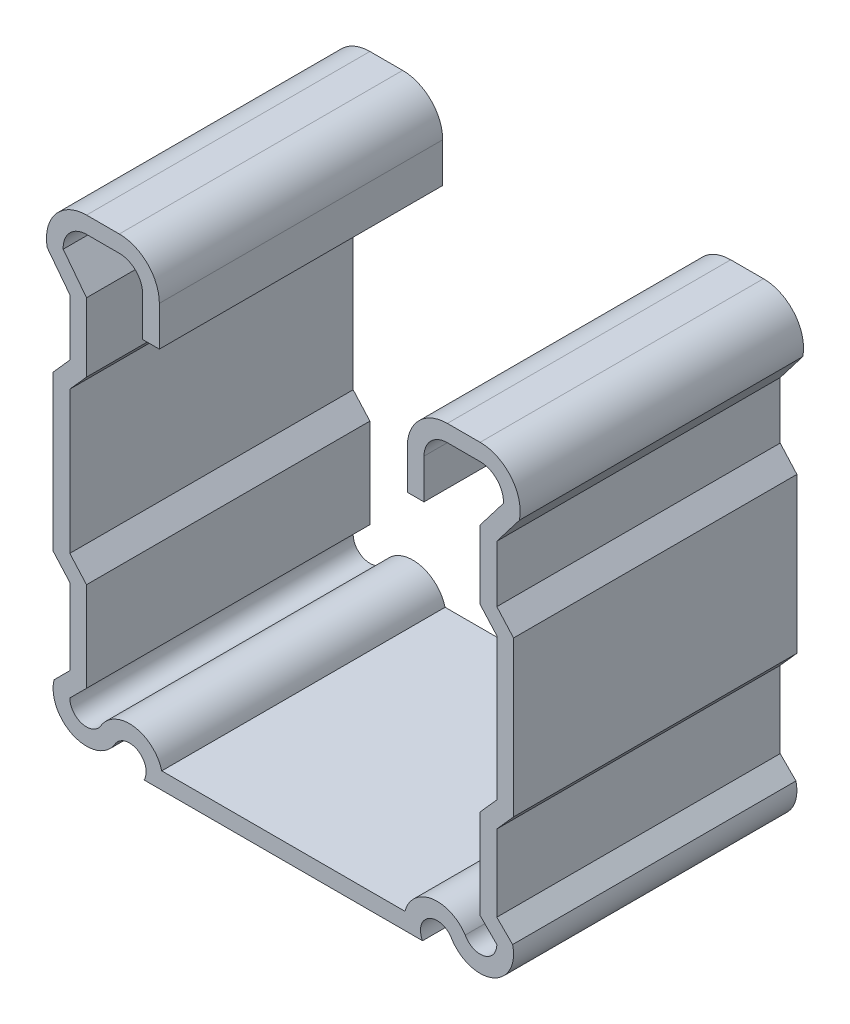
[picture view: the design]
ISO-10303-21;
HEADER;
FILE_DESCRIPTION(('STEP AP214'),'2;1');
FILE_NAME('part.step','',(''),(''),'','','');
FILE_SCHEMA(('AUTOMOTIVE_DESIGN { 1 0 10303 214 1 1 1 1 }'));
ENDSEC;
DATA;
#1=APPLICATION_CONTEXT('core data for automotive mechanical design processes');
#2=APPLICATION_PROTOCOL_DEFINITION('international standard','automotive_design',2000,#1);
#3=PRODUCT_CONTEXT('',#1,'mechanical');
#4=PRODUCT('Part','Part','',(#3));
#5=PRODUCT_RELATED_PRODUCT_CATEGORY('part','',(#4));
#6=PRODUCT_DEFINITION_FORMATION('','',#4);
#7=PRODUCT_DEFINITION_CONTEXT('part definition',#1,'design');
#8=PRODUCT_DEFINITION('design','',#6,#7);
#9=PRODUCT_DEFINITION_SHAPE('','',#8);
#10=(LENGTH_UNIT() NAMED_UNIT(*) SI_UNIT(.MILLI.,.METRE.));
#11=(NAMED_UNIT(*) PLANE_ANGLE_UNIT() SI_UNIT($,.RADIAN.));
#12=(NAMED_UNIT(*) SI_UNIT($,.STERADIAN.) SOLID_ANGLE_UNIT());
#13=UNCERTAINTY_MEASURE_WITH_UNIT(LENGTH_MEASURE(1.E-05),#10,'distance_accuracy_value','');
#14=(GEOMETRIC_REPRESENTATION_CONTEXT(3) GLOBAL_UNCERTAINTY_ASSIGNED_CONTEXT((#13)) GLOBAL_UNIT_ASSIGNED_CONTEXT((#10,
#11,#12)) REPRESENTATION_CONTEXT('',''));
#15=CARTESIAN_POINT('',(0.,0.,0.));
#16=DIRECTION('',(0.,0.,1.));
#17=DIRECTION('',(1.,0.,0.));
#18=AXIS2_PLACEMENT_3D('',#15,#16,#17);
#19=CARTESIAN_POINT('',(13.7938113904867,-17.794678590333,12.7));
#20=DIRECTION('',(0.,0.,-1.));
#21=DIRECTION('',(-1.,0.,0.));
#22=AXIS2_PLACEMENT_3D('',#19,#20,#21);
#23=CYLINDRICAL_SURFACE('',#22,2.9972);
#24=CARTESIAN_POINT('',(13.7938113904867,-17.794678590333,-12.7));
#25=DIRECTION('',(0.,0.,1.));
#26=DIRECTION('',(1.,0.,0.));
#27=AXIS2_PLACEMENT_3D('',#24,#25,#26);
#28=CIRCLE('',#27,2.9972);
#29=CARTESIAN_POINT('',(16.3051886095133,-16.158771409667,-12.7));
#30=VERTEX_POINT('',#29);
#31=CARTESIAN_POINT('',(10.8989921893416,-17.018,-12.7));
#32=VERTEX_POINT('',#31);
#33=EDGE_CURVE('E417',#30,#32,#28,.T.);
#34=ORIENTED_EDGE('',*,*,#33,.T.);
#35=DIRECTION('',(0.,0.,-1.));
#36=VECTOR('',#35,1.);
#37=CARTESIAN_POINT('',(10.8989921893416,-17.018,12.7));
#38=LINE('',#37,#36);
#39=CARTESIAN_POINT('',(10.8989921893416,-17.018,12.7));
#40=VERTEX_POINT('',#39);
#41=EDGE_CURVE('E11',#40,#32,#38,.T.);
#42=ORIENTED_EDGE('',*,*,#41,.F.);
#43=CARTESIAN_POINT('',(13.7938113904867,-17.794678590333,12.7));
#44=DIRECTION('',(0.,0.,1.));
#45=DIRECTION('',(1.,0.,0.));
#46=AXIS2_PLACEMENT_3D('',#43,#44,#45);
#47=CIRCLE('',#46,2.9972);
#48=CARTESIAN_POINT('',(16.3051886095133,-16.158771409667,12.7));
#49=VERTEX_POINT('',#48);
#50=EDGE_CURVE('E527',#49,#40,#47,.T.);
#51=ORIENTED_EDGE('',*,*,#50,.F.);
#52=DIRECTION('',(0.,0.,-1.));
#53=VECTOR('',#52,1.);
#54=CARTESIAN_POINT('',(16.3051886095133,-16.158771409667,12.7));
#55=LINE('',#54,#53);
#56=EDGE_CURVE('E413',#49,#30,#55,.T.);
#57=ORIENTED_EDGE('',*,*,#56,.T.);
#58=EDGE_LOOP('',(#34,#42,#51,#57));
#59=FACE_BOUND('',#58,.T.);
#60=ADVANCED_FACE('F33',(#59),#23,.T.);
#61=CARTESIAN_POINT('',(-10.8989921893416,-17.018,12.7));
#62=DIRECTION('',(0.,-1.,0.));
#63=DIRECTION('',(1.,0.,0.));
#64=AXIS2_PLACEMENT_3D('',#61,#62,#63);
#65=PLANE('',#64);
#66=DIRECTION('',(-1.,0.,0.));
#67=VECTOR('',#66,1.);
#68=CARTESIAN_POINT('',(-10.8989921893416,-17.018,-12.7));
#69=LINE('',#68,#67);
#70=CARTESIAN_POINT('',(-10.8989921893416,-17.018,-12.7));
#71=VERTEX_POINT('',#70);
#72=EDGE_CURVE('E420',#32,#71,#69,.T.);
#73=ORIENTED_EDGE('',*,*,#72,.T.);
#74=DIRECTION('',(0.,0.,-1.));
#75=VECTOR('',#74,1.);
#76=CARTESIAN_POINT('',(-10.8989921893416,-17.018,12.7));
#77=LINE('',#76,#75);
#78=CARTESIAN_POINT('',(-10.8989921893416,-17.018,12.7));
#79=VERTEX_POINT('',#78);
#80=EDGE_CURVE('E41',#79,#71,#77,.T.);
#81=ORIENTED_EDGE('',*,*,#80,.F.);
#82=DIRECTION('',(-1.,0.,0.));
#83=VECTOR('',#82,1.);
#84=CARTESIAN_POINT('',(-10.8989921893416,-17.018,12.7));
#85=LINE('',#84,#83);
#86=EDGE_CURVE('E236',#40,#79,#85,.T.);
#87=ORIENTED_EDGE('',*,*,#86,.F.);
#88=ORIENTED_EDGE('',*,*,#41,.T.);
#89=EDGE_LOOP('',(#73,#81,#87,#88));
#90=FACE_BOUND('',#89,.T.);
#91=ADVANCED_FACE('F825',(#90),#65,.F.);
#92=CARTESIAN_POINT('',(-13.7938113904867,-17.794678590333,12.7));
#93=DIRECTION('',(0.,0.,-1.));
#94=DIRECTION('',(-1.,0.,0.));
#95=AXIS2_PLACEMENT_3D('',#92,#93,#94);
#96=CYLINDRICAL_SURFACE('',#95,2.9972);
#97=CARTESIAN_POINT('',(-13.7938113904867,-17.794678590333,-12.7));
#98=DIRECTION('',(0.,0.,1.));
#99=DIRECTION('',(-1.,0.,0.));
#100=AXIS2_PLACEMENT_3D('',#97,#98,#99);
#101=CIRCLE('',#100,2.9972);
#102=CARTESIAN_POINT('',(-16.4142858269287,-16.3399203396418,-12.7));
#103=VERTEX_POINT('',#102);
#104=EDGE_CURVE('E422',#71,#103,#101,.T.);
#105=ORIENTED_EDGE('',*,*,#104,.T.);
#106=DIRECTION('',(0.,0.,-1.));
#107=VECTOR('',#106,1.);
#108=CARTESIAN_POINT('',(-16.4142858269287,-16.3399203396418,12.7));
#109=LINE('',#108,#107);
#110=CARTESIAN_POINT('',(-16.4142858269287,-16.3399203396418,12.7));
#111=VERTEX_POINT('',#110);
#112=EDGE_CURVE('E678',#111,#103,#109,.T.);
#113=ORIENTED_EDGE('',*,*,#112,.F.);
#114=CARTESIAN_POINT('',(-13.7938113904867,-17.794678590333,12.7));
#115=DIRECTION('',(0.,0.,1.));
#116=DIRECTION('',(-1.,0.,0.));
#117=AXIS2_PLACEMENT_3D('',#114,#115,#116);
#118=CIRCLE('',#117,2.9972);
#119=EDGE_CURVE('E686',#79,#111,#118,.T.);
#120=ORIENTED_EDGE('',*,*,#119,.F.);
#121=ORIENTED_EDGE('',*,*,#80,.T.);
#122=EDGE_LOOP('',(#105,#113,#120,#121));
#123=FACE_BOUND('',#122,.T.);
#124=ADVANCED_FACE('F684',(#123),#96,.T.);
#125=CARTESIAN_POINT('',(-17.6403,-15.478125,12.7));
#126=DIRECTION('',(0.,0.,-1.));
#127=DIRECTION('',(-1.,0.,0.));
#128=AXIS2_PLACEMENT_3D('',#125,#126,#127);
#129=CYLINDRICAL_SURFACE('',#128,1.4986);
#130=CARTESIAN_POINT('',(-17.6403,-15.478125,-12.7));
#131=DIRECTION('',(0.,0.,-1.));
#132=DIRECTION('',(1.,0.,0.));
#133=AXIS2_PLACEMENT_3D('',#130,#131,#132);
#134=CIRCLE('',#133,1.4986);
#135=CARTESIAN_POINT('',(-19.1389,-15.478125,-12.7));
#136=VERTEX_POINT('',#135);
#137=EDGE_CURVE('E424',#103,#136,#134,.T.);
#138=ORIENTED_EDGE('',*,*,#137,.T.);
#139=DIRECTION('',(0.,0.,-1.));
#140=VECTOR('',#139,1.);
#141=CARTESIAN_POINT('',(-19.1389,-15.478125,12.7));
#142=LINE('',#141,#140);
#143=CARTESIAN_POINT('',(-19.1389,-15.478125,12.7));
#144=VERTEX_POINT('',#143);
#145=EDGE_CURVE('E675',#144,#136,#142,.T.);
#146=ORIENTED_EDGE('',*,*,#145,.F.);
#147=CARTESIAN_POINT('',(-17.6403,-15.478125,12.7));
#148=DIRECTION('',(0.,0.,-1.));
#149=DIRECTION('',(1.,0.,0.));
#150=AXIS2_PLACEMENT_3D('',#147,#148,#149);
#151=CIRCLE('',#150,1.4986);
#152=EDGE_CURVE('E704',#111,#144,#151,.T.);
#153=ORIENTED_EDGE('',*,*,#152,.F.);
#154=ORIENTED_EDGE('',*,*,#112,.T.);
#155=EDGE_LOOP('',(#138,#146,#153,#154));
#156=FACE_BOUND('',#155,.T.);
#157=ADVANCED_FACE('F695',(#156),#129,.F.);
#158=CARTESIAN_POINT('',(-17.6403,-13.979525,12.7));
#159=DIRECTION('',(-0.707106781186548,0.707106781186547,0.));
#160=DIRECTION('',(-0.707106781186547,-0.707106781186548,0.));
#161=AXIS2_PLACEMENT_3D('',#158,#159,#160);
#162=PLANE('',#161);
#163=DIRECTION('',(0.707106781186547,0.707106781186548,0.));
#164=VECTOR('',#163,1.);
#165=CARTESIAN_POINT('',(-17.6403,-13.979525,-12.7));
#166=LINE('',#165,#164);
#167=CARTESIAN_POINT('',(-17.6403,-13.979525,-12.7));
#168=VERTEX_POINT('',#167);
#169=EDGE_CURVE('E426',#136,#168,#166,.T.);
#170=ORIENTED_EDGE('',*,*,#169,.T.);
#171=DIRECTION('',(0.,0.,-1.));
#172=VECTOR('',#171,1.);
#173=CARTESIAN_POINT('',(-17.6403,-13.979525,12.7));
#174=LINE('',#173,#172);
#175=CARTESIAN_POINT('',(-17.6403,-13.979525,12.7));
#176=VERTEX_POINT('',#175);
#177=EDGE_CURVE('E672',#176,#168,#174,.T.);
#178=ORIENTED_EDGE('',*,*,#177,.F.);
#179=DIRECTION('',(0.707106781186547,0.707106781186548,0.));
#180=VECTOR('',#179,1.);
#181=CARTESIAN_POINT('',(-17.6403,-13.979525,12.7));
#182=LINE('',#181,#180);
#183=EDGE_CURVE('E701',#144,#176,#182,.T.);
#184=ORIENTED_EDGE('',*,*,#183,.F.);
#185=ORIENTED_EDGE('',*,*,#145,.T.);
#186=EDGE_LOOP('',(#170,#178,#184,#185));
#187=FACE_BOUND('',#186,.T.);
#188=ADVANCED_FACE('F699',(#187),#162,.F.);
#189=CARTESIAN_POINT('',(-17.6403,-13.979525,12.7));
#190=DIRECTION('',(-1.,0.,0.));
#191=DIRECTION('',(0.,-1.,0.));
#192=AXIS2_PLACEMENT_3D('',#189,#190,#191);
#193=PLANE('',#192);
#194=DIRECTION('',(0.,1.,0.));
#195=VECTOR('',#194,1.);
#196=CARTESIAN_POINT('',(-17.6403,-13.979525,-12.7));
#197=LINE('',#196,#195);
#198=CARTESIAN_POINT('',(-17.6403,-5.93680201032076,-12.7));
#199=VERTEX_POINT('',#198);
#200=EDGE_CURVE('E428',#168,#199,#197,.T.);
#201=ORIENTED_EDGE('',*,*,#200,.T.);
#202=DIRECTION('',(0.,0.,-1.));
#203=VECTOR('',#202,1.);
#204=CARTESIAN_POINT('',(-17.6403,-5.93680201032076,12.7));
#205=LINE('',#204,#203);
#206=CARTESIAN_POINT('',(-17.6403,-5.93680201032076,12.7));
#207=VERTEX_POINT('',#206);
#208=EDGE_CURVE('E669',#207,#199,#205,.T.);
#209=ORIENTED_EDGE('',*,*,#208,.F.);
#210=DIRECTION('',(0.,1.,0.));
#211=VECTOR('',#210,1.);
#212=CARTESIAN_POINT('',(-17.6403,-13.979525,12.7));
#213=LINE('',#212,#211);
#214=EDGE_CURVE('E703',#176,#207,#213,.T.);
#215=ORIENTED_EDGE('',*,*,#214,.F.);
#216=ORIENTED_EDGE('',*,*,#177,.T.);
#217=EDGE_LOOP('',(#201,#209,#215,#216));
#218=FACE_BOUND('',#217,.T.);
#219=ADVANCED_FACE('F838',(#218),#193,.F.);
#220=CARTESIAN_POINT('',(-17.6403,-5.93680201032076,12.7));
#221=DIRECTION('',(-0.746819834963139,-0.665026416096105,0.));
#222=DIRECTION('',(0.665026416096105,-0.746819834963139,0.));
#223=AXIS2_PLACEMENT_3D('',#220,#221,#222);
#224=PLANE('',#223);
#225=DIRECTION('',(-0.665026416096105,0.746819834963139,0.));
#226=VECTOR('',#225,1.);
#227=CARTESIAN_POINT('',(-17.6403,-5.93680201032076,-12.7));
#228=LINE('',#227,#226);
#229=CARTESIAN_POINT('',(-19.1389,-4.25388509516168,-12.7));
#230=VERTEX_POINT('',#229);
#231=EDGE_CURVE('E430',#199,#230,#228,.T.);
#232=ORIENTED_EDGE('',*,*,#231,.T.);
#233=DIRECTION('',(0.,0.,-1.));
#234=VECTOR('',#233,1.);
#235=CARTESIAN_POINT('',(-19.1389,-4.25388509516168,12.7));
#236=LINE('',#235,#234);
#237=CARTESIAN_POINT('',(-19.1389,-4.25388509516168,12.7));
#238=VERTEX_POINT('',#237);
#239=EDGE_CURVE('E666',#238,#230,#236,.T.);
#240=ORIENTED_EDGE('',*,*,#239,.F.);
#241=DIRECTION('',(-0.665026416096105,0.746819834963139,0.));
#242=VECTOR('',#241,1.);
#243=CARTESIAN_POINT('',(-17.6403,-5.93680201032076,12.7));
#244=LINE('',#243,#242);
#245=EDGE_CURVE('E706',#207,#238,#244,.T.);
#246=ORIENTED_EDGE('',*,*,#245,.F.);
#247=ORIENTED_EDGE('',*,*,#208,.T.);
#248=EDGE_LOOP('',(#232,#240,#246,#247));
#249=FACE_BOUND('',#248,.T.);
#250=ADVANCED_FACE('F841',(#249),#224,.F.);
#251=CARTESIAN_POINT('',(-19.1389,-4.25388509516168,12.7));
#252=DIRECTION('',(-1.,0.,0.));
#253=DIRECTION('',(0.,0.,1.));
#254=AXIS2_PLACEMENT_3D('',#251,#252,#253);
#255=PLANE('',#254);
#256=DIRECTION('',(0.,1.,0.));
#257=VECTOR('',#256,1.);
#258=CARTESIAN_POINT('',(-19.1389,-4.25388509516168,-12.7));
#259=LINE('',#258,#257);
#260=CARTESIAN_POINT('',(-19.1389,8.49568509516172,-12.7));
#261=VERTEX_POINT('',#260);
#262=EDGE_CURVE('E432',#230,#261,#259,.T.);
#263=ORIENTED_EDGE('',*,*,#262,.T.);
#264=DIRECTION('',(0.,0.,-1.));
#265=VECTOR('',#264,1.);
#266=CARTESIAN_POINT('',(-19.1389,8.49568509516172,12.7));
#267=LINE('',#266,#265);
#268=CARTESIAN_POINT('',(-19.1389,8.49568509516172,12.7));
#269=VERTEX_POINT('',#268);
#270=EDGE_CURVE('E663',#269,#261,#267,.T.);
#271=ORIENTED_EDGE('',*,*,#270,.F.);
#272=DIRECTION('',(0.,1.,0.));
#273=VECTOR('',#272,1.);
#274=CARTESIAN_POINT('',(-19.1389,-4.25388509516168,12.7));
#275=LINE('',#274,#273);
#276=EDGE_CURVE('E712',#238,#269,#275,.T.);
#277=ORIENTED_EDGE('',*,*,#276,.F.);
#278=ORIENTED_EDGE('',*,*,#239,.T.);
#279=EDGE_LOOP('',(#263,#271,#277,#278));
#280=FACE_BOUND('',#279,.T.);
#281=ADVANCED_FACE('F845',(#280),#255,.F.);
#282=CARTESIAN_POINT('',(-17.6403,10.178602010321,12.7));
#283=DIRECTION('',(-0.746819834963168,0.665026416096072,0.));
#284=DIRECTION('',(-0.665026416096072,-0.746819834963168,0.));
#285=AXIS2_PLACEMENT_3D('',#282,#283,#284);
#286=PLANE('',#285);
#287=DIRECTION('',(0.665026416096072,0.746819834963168,0.));
#288=VECTOR('',#287,1.);
#289=CARTESIAN_POINT('',(-17.6403,10.178602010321,-12.7));
#290=LINE('',#289,#288);
#291=CARTESIAN_POINT('',(-17.6403,10.178602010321,-12.7));
#292=VERTEX_POINT('',#291);
#293=EDGE_CURVE('E434',#261,#292,#290,.T.);
#294=ORIENTED_EDGE('',*,*,#293,.T.);
#295=DIRECTION('',(0.,0.,-1.));
#296=VECTOR('',#295,1.);
#297=CARTESIAN_POINT('',(-17.6403,10.178602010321,12.7));
#298=LINE('',#297,#296);
#299=CARTESIAN_POINT('',(-17.6403,10.178602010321,12.7));
#300=VERTEX_POINT('',#299);
#301=EDGE_CURVE('E660',#300,#292,#298,.T.);
#302=ORIENTED_EDGE('',*,*,#301,.F.);
#303=DIRECTION('',(0.665026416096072,0.746819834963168,0.));
#304=VECTOR('',#303,1.);
#305=CARTESIAN_POINT('',(-17.6403,10.178602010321,12.7));
#306=LINE('',#305,#304);
#307=EDGE_CURVE('E714',#269,#300,#306,.T.);
#308=ORIENTED_EDGE('',*,*,#307,.F.);
#309=ORIENTED_EDGE('',*,*,#270,.T.);
#310=EDGE_LOOP('',(#294,#302,#308,#309));
#311=FACE_BOUND('',#310,.T.);
#312=ADVANCED_FACE('F849',(#311),#286,.F.);
#313=CARTESIAN_POINT('',(-17.6403,10.178602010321,12.7));
#314=DIRECTION('',(-1.,0.,0.));
#315=DIRECTION('',(0.,0.,1.));
#316=AXIS2_PLACEMENT_3D('',#313,#314,#315);
#317=PLANE('',#316);
#318=DIRECTION('',(0.,1.,0.));
#319=VECTOR('',#318,1.);
#320=CARTESIAN_POINT('',(-17.6403,10.178602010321,-12.7));
#321=LINE('',#320,#319);
#322=CARTESIAN_POINT('',(-17.6403,16.3392865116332,-12.7));
#323=VERTEX_POINT('',#322);
#324=EDGE_CURVE('E436',#292,#323,#321,.T.);
#325=ORIENTED_EDGE('',*,*,#324,.T.);
#326=DIRECTION('',(0.,0.,-1.));
#327=VECTOR('',#326,1.);
#328=CARTESIAN_POINT('',(-17.6403,16.3392865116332,12.7));
#329=LINE('',#328,#327);
#330=CARTESIAN_POINT('',(-17.6403,16.3392865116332,12.7));
#331=VERTEX_POINT('',#330);
#332=EDGE_CURVE('E657',#331,#323,#329,.T.);
#333=ORIENTED_EDGE('',*,*,#332,.F.);
#334=DIRECTION('',(0.,1.,0.));
#335=VECTOR('',#334,1.);
#336=CARTESIAN_POINT('',(-17.6403,10.178602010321,12.7));
#337=LINE('',#336,#335);
#338=EDGE_CURVE('E716',#300,#331,#337,.T.);
#339=ORIENTED_EDGE('',*,*,#338,.F.);
#340=ORIENTED_EDGE('',*,*,#301,.T.);
#341=EDGE_LOOP('',(#325,#333,#339,#340));
#342=FACE_BOUND('',#341,.T.);
#343=ADVANCED_FACE('F853',(#342),#317,.F.);
#344=CARTESIAN_POINT('',(-17.6403,16.3392865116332,12.7));
#345=DIRECTION('',(-0.793466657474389,-0.608613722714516,0.));
#346=DIRECTION('',(0.608613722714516,-0.793466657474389,0.));
#347=AXIS2_PLACEMENT_3D('',#344,#345,#346);
#348=PLANE('',#347);
#349=DIRECTION('',(-0.608613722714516,0.793466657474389,0.));
#350=VECTOR('',#349,1.);
#351=CARTESIAN_POINT('',(-17.6403,16.3392865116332,-12.7));
#352=LINE('',#351,#350);
#353=CARTESIAN_POINT('',(-19.7298825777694,19.0635335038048,-12.7));
#354=VERTEX_POINT('',#353);
#355=EDGE_CURVE('E438',#323,#354,#352,.T.);
#356=ORIENTED_EDGE('',*,*,#355,.T.);
#357=DIRECTION('',(0.,0.,-1.));
#358=VECTOR('',#357,1.);
#359=CARTESIAN_POINT('',(-19.7298825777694,19.0635335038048,12.7));
#360=LINE('',#359,#358);
#361=CARTESIAN_POINT('',(-19.7298825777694,19.0635335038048,12.7));
#362=VERTEX_POINT('',#361);
#363=EDGE_CURVE('E654',#362,#354,#360,.T.);
#364=ORIENTED_EDGE('',*,*,#363,.F.);
#365=DIRECTION('',(-0.608613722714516,0.793466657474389,0.));
#366=VECTOR('',#365,1.);
#367=CARTESIAN_POINT('',(-17.6403,16.3392865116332,12.7));
#368=LINE('',#367,#366);
#369=EDGE_CURVE('E718',#331,#362,#368,.T.);
#370=ORIENTED_EDGE('',*,*,#369,.F.);
#371=ORIENTED_EDGE('',*,*,#332,.T.);
#372=EDGE_LOOP('',(#356,#364,#370,#371));
#373=FACE_BOUND('',#372,.T.);
#374=ADVANCED_FACE('F857',(#373),#348,.F.);
#375=CARTESIAN_POINT('',(-17.6403,19.1676263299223,12.7));
#376=DIRECTION('',(0.,0.,-1.));
#377=DIRECTION('',(-1.,0.,0.));
#378=AXIS2_PLACEMENT_3D('',#375,#376,#377);
#379=CYLINDRICAL_SURFACE('',#378,2.09217367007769);
#380=CARTESIAN_POINT('',(-17.6403,19.1676263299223,-12.7));
#381=DIRECTION('',(0.,0.,-1.));
#382=DIRECTION('',(1.,0.,0.));
#383=AXIS2_PLACEMENT_3D('',#380,#381,#382);
#384=CIRCLE('',#383,2.09217367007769);
#385=CARTESIAN_POINT('',(-17.6403,21.2598,-12.7));
#386=VERTEX_POINT('',#385);
#387=EDGE_CURVE('E440',#354,#386,#384,.T.);
#388=ORIENTED_EDGE('',*,*,#387,.T.);
#389=DIRECTION('',(0.,0.,-1.));
#390=VECTOR('',#389,1.);
#391=CARTESIAN_POINT('',(-17.6403,21.2598,12.7));
#392=LINE('',#391,#390);
#393=CARTESIAN_POINT('',(-17.6403,21.2598,12.7));
#394=VERTEX_POINT('',#393);
#395=EDGE_CURVE('E651',#394,#386,#392,.T.);
#396=ORIENTED_EDGE('',*,*,#395,.F.);
#397=CARTESIAN_POINT('',(-17.6403,19.1676263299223,12.7));
#398=DIRECTION('',(0.,0.,-1.));
#399=DIRECTION('',(1.,0.,0.));
#400=AXIS2_PLACEMENT_3D('',#397,#398,#399);
#401=CIRCLE('',#400,2.09217367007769);
#402=EDGE_CURVE('E720',#362,#394,#401,.T.);
#403=ORIENTED_EDGE('',*,*,#402,.F.);
#404=ORIENTED_EDGE('',*,*,#363,.T.);
#405=EDGE_LOOP('',(#388,#396,#403,#404));
#406=FACE_BOUND('',#405,.T.);
#407=ADVANCED_FACE('F861',(#406),#379,.F.);
#408=CARTESIAN_POINT('',(-17.6403,21.2598,12.7));
#409=DIRECTION('',(0.,1.,0.));
#410=DIRECTION('',(0.,0.,1.));
#411=AXIS2_PLACEMENT_3D('',#408,#409,#410);
#412=PLANE('',#411);
#413=DIRECTION('',(1.,0.,0.));
#414=VECTOR('',#413,1.);
#415=CARTESIAN_POINT('',(-17.6403,21.2598,-12.7));
#416=LINE('',#415,#414);
#417=CARTESIAN_POINT('',(-14.7032736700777,21.2598,-12.7));
#418=VERTEX_POINT('',#417);
#419=EDGE_CURVE('E442',#386,#418,#416,.T.);
#420=ORIENTED_EDGE('',*,*,#419,.T.);
#421=DIRECTION('',(0.,0.,-1.));
#422=VECTOR('',#421,1.);
#423=CARTESIAN_POINT('',(-14.7032736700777,21.2598,12.7));
#424=LINE('',#423,#422);
#425=CARTESIAN_POINT('',(-14.7032736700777,21.2598,12.7));
#426=VERTEX_POINT('',#425);
#427=EDGE_CURVE('E648',#426,#418,#424,.T.);
#428=ORIENTED_EDGE('',*,*,#427,.F.);
#429=DIRECTION('',(1.,0.,0.));
#430=VECTOR('',#429,1.);
#431=CARTESIAN_POINT('',(-17.6403,21.2598,12.7));
#432=LINE('',#431,#430);
#433=EDGE_CURVE('E722',#394,#426,#432,.T.);
#434=ORIENTED_EDGE('',*,*,#433,.F.);
#435=ORIENTED_EDGE('',*,*,#395,.T.);
#436=EDGE_LOOP('',(#420,#428,#434,#435));
#437=FACE_BOUND('',#436,.T.);
#438=ADVANCED_FACE('F865',(#437),#412,.F.);
#439=CARTESIAN_POINT('',(-14.7032736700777,19.1676263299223,12.7));
#440=DIRECTION('',(0.,0.,-1.));
#441=DIRECTION('',(-1.,0.,0.));
#442=AXIS2_PLACEMENT_3D('',#439,#440,#441);
#443=CYLINDRICAL_SURFACE('',#442,2.09217367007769);
#444=CARTESIAN_POINT('',(-14.7032736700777,19.1676263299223,-12.7));
#445=DIRECTION('',(0.,0.,-1.));
#446=DIRECTION('',(1.,0.,0.));
#447=AXIS2_PLACEMENT_3D('',#444,#445,#446);
#448=CIRCLE('',#447,2.09217367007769);
#449=CARTESIAN_POINT('',(-12.6111,19.1676263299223,-12.7));
#450=VERTEX_POINT('',#449);
#451=EDGE_CURVE('E444',#418,#450,#448,.T.);
#452=ORIENTED_EDGE('',*,*,#451,.T.);
#453=DIRECTION('',(0.,0.,-1.));
#454=VECTOR('',#453,1.);
#455=CARTESIAN_POINT('',(-12.6111,19.1676263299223,12.7));
#456=LINE('',#455,#454);
#457=CARTESIAN_POINT('',(-12.6111,19.1676263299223,12.7));
#458=VERTEX_POINT('',#457);
#459=EDGE_CURVE('E645',#458,#450,#456,.T.);
#460=ORIENTED_EDGE('',*,*,#459,.F.);
#461=CARTESIAN_POINT('',(-14.7032736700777,19.1676263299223,12.7));
#462=DIRECTION('',(0.,0.,-1.));
#463=DIRECTION('',(1.,0.,0.));
#464=AXIS2_PLACEMENT_3D('',#461,#462,#463);
#465=CIRCLE('',#464,2.09217367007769);
#466=EDGE_CURVE('E724',#426,#458,#465,.T.);
#467=ORIENTED_EDGE('',*,*,#466,.F.);
#468=ORIENTED_EDGE('',*,*,#427,.T.);
#469=EDGE_LOOP('',(#452,#460,#467,#468));
#470=FACE_BOUND('',#469,.T.);
#471=ADVANCED_FACE('F869',(#470),#443,.F.);
#472=CARTESIAN_POINT('',(-12.6111,19.1676263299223,12.7));
#473=DIRECTION('',(1.,0.,0.));
#474=DIRECTION('',(0.,0.,-1.));
#475=AXIS2_PLACEMENT_3D('',#472,#473,#474);
#476=PLANE('',#475);
#477=DIRECTION('',(0.,-1.,0.));
#478=VECTOR('',#477,1.);
#479=CARTESIAN_POINT('',(-12.6111,19.1676263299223,-12.7));
#480=LINE('',#479,#478);
#481=CARTESIAN_POINT('',(-12.6111,15.61465,-12.7));
#482=VERTEX_POINT('',#481);
#483=EDGE_CURVE('E446',#450,#482,#480,.T.);
#484=ORIENTED_EDGE('',*,*,#483,.T.);
#485=DIRECTION('',(0.,0.,-1.));
#486=VECTOR('',#485,1.);
#487=CARTESIAN_POINT('',(-12.6111,15.61465,12.7));
#488=LINE('',#487,#486);
#489=CARTESIAN_POINT('',(-12.6111,15.61465,12.7));
#490=VERTEX_POINT('',#489);
#491=EDGE_CURVE('E642',#490,#482,#488,.T.);
#492=ORIENTED_EDGE('',*,*,#491,.F.);
#493=DIRECTION('',(0.,-1.,0.));
#494=VECTOR('',#493,1.);
#495=CARTESIAN_POINT('',(-12.6111,19.1676263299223,12.7));
#496=LINE('',#495,#494);
#497=EDGE_CURVE('E726',#458,#490,#496,.T.);
#498=ORIENTED_EDGE('',*,*,#497,.F.);
#499=ORIENTED_EDGE('',*,*,#459,.T.);
#500=EDGE_LOOP('',(#484,#492,#498,#499));
#501=FACE_BOUND('',#500,.T.);
#502=ADVANCED_FACE('F873',(#501),#476,.F.);
#503=CARTESIAN_POINT('',(-12.6111,15.61465,12.7));
#504=DIRECTION('',(0.,1.,0.));
#505=DIRECTION('',(0.,0.,1.));
#506=AXIS2_PLACEMENT_3D('',#503,#504,#505);
#507=PLANE('',#506);
#508=DIRECTION('',(1.,0.,0.));
#509=VECTOR('',#508,1.);
#510=CARTESIAN_POINT('',(-12.6111,15.61465,-12.7));
#511=LINE('',#510,#509);
#512=CARTESIAN_POINT('',(-11.1125,15.61465,-12.7));
#513=VERTEX_POINT('',#512);
#514=EDGE_CURVE('E448',#482,#513,#511,.T.);
#515=ORIENTED_EDGE('',*,*,#514,.T.);
#516=DIRECTION('',(0.,0.,-1.));
#517=VECTOR('',#516,1.);
#518=CARTESIAN_POINT('',(-11.1125,15.61465,12.7));
#519=LINE('',#518,#517);
#520=CARTESIAN_POINT('',(-11.1125,15.61465,12.7));
#521=VERTEX_POINT('',#520);
#522=EDGE_CURVE('E639',#521,#513,#519,.T.);
#523=ORIENTED_EDGE('',*,*,#522,.F.);
#524=DIRECTION('',(1.,0.,0.));
#525=VECTOR('',#524,1.);
#526=CARTESIAN_POINT('',(-12.6111,15.61465,12.7));
#527=LINE('',#526,#525);
#528=EDGE_CURVE('E728',#490,#521,#527,.T.);
#529=ORIENTED_EDGE('',*,*,#528,.F.);
#530=ORIENTED_EDGE('',*,*,#491,.T.);
#531=EDGE_LOOP('',(#515,#523,#529,#530));
#532=FACE_BOUND('',#531,.T.);
#533=ADVANCED_FACE('F877',(#532),#507,.F.);
#534=CARTESIAN_POINT('',(-11.1125,19.1676263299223,12.7));
#535=DIRECTION('',(-1.,0.,0.));
#536=DIRECTION('',(0.,0.,1.));
#537=AXIS2_PLACEMENT_3D('',#534,#535,#536);
#538=PLANE('',#537);
#539=DIRECTION('',(0.,1.,0.));
#540=VECTOR('',#539,1.);
#541=CARTESIAN_POINT('',(-11.1125,19.1676263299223,-12.7));
#542=LINE('',#541,#540);
#543=CARTESIAN_POINT('',(-11.1125,19.1676263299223,-12.7));
#544=VERTEX_POINT('',#543);
#545=EDGE_CURVE('E450',#513,#544,#542,.T.);
#546=ORIENTED_EDGE('',*,*,#545,.T.);
#547=DIRECTION('',(0.,0.,-1.));
#548=VECTOR('',#547,1.);
#549=CARTESIAN_POINT('',(-11.1125,19.1676263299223,12.7));
#550=LINE('',#549,#548);
#551=CARTESIAN_POINT('',(-11.1125,19.1676263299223,12.7));
#552=VERTEX_POINT('',#551);
#553=EDGE_CURVE('E636',#552,#544,#550,.T.);
#554=ORIENTED_EDGE('',*,*,#553,.F.);
#555=DIRECTION('',(0.,1.,0.));
#556=VECTOR('',#555,1.);
#557=CARTESIAN_POINT('',(-11.1125,19.1676263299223,12.7));
#558=LINE('',#557,#556);
#559=EDGE_CURVE('E730',#521,#552,#558,.T.);
#560=ORIENTED_EDGE('',*,*,#559,.F.);
#561=ORIENTED_EDGE('',*,*,#522,.T.);
#562=EDGE_LOOP('',(#546,#554,#560,#561));
#563=FACE_BOUND('',#562,.T.);
#564=ADVANCED_FACE('F881',(#563),#538,.F.);
#565=CARTESIAN_POINT('',(-14.7032736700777,19.1676263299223,12.7));
#566=DIRECTION('',(0.,0.,-1.));
#567=DIRECTION('',(-1.,0.,0.));
#568=AXIS2_PLACEMENT_3D('',#565,#566,#567);
#569=CYLINDRICAL_SURFACE('',#568,3.59077367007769);
#570=CARTESIAN_POINT('',(-14.7032736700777,19.1676263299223,-12.7));
#571=DIRECTION('',(0.,0.,1.));
#572=DIRECTION('',(1.,0.,0.));
#573=AXIS2_PLACEMENT_3D('',#570,#571,#572);
#574=CIRCLE('',#573,3.59077367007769);
#575=CARTESIAN_POINT('',(-14.7032736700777,22.7584,-12.7));
#576=VERTEX_POINT('',#575);
#577=EDGE_CURVE('E452',#544,#576,#574,.T.);
#578=ORIENTED_EDGE('',*,*,#577,.T.);
#579=DIRECTION('',(0.,0.,-1.));
#580=VECTOR('',#579,1.);
#581=CARTESIAN_POINT('',(-14.7032736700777,22.7584,12.7));
#582=LINE('',#581,#580);
#583=CARTESIAN_POINT('',(-14.7032736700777,22.7584,12.7));
#584=VERTEX_POINT('',#583);
#585=EDGE_CURVE('E633',#584,#576,#582,.T.);
#586=ORIENTED_EDGE('',*,*,#585,.F.);
#587=CARTESIAN_POINT('',(-14.7032736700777,19.1676263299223,12.7));
#588=DIRECTION('',(0.,0.,1.));
#589=DIRECTION('',(1.,0.,0.));
#590=AXIS2_PLACEMENT_3D('',#587,#588,#589);
#591=CIRCLE('',#590,3.59077367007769);
#592=EDGE_CURVE('E732',#552,#584,#591,.T.);
#593=ORIENTED_EDGE('',*,*,#592,.F.);
#594=ORIENTED_EDGE('',*,*,#553,.T.);
#595=EDGE_LOOP('',(#578,#586,#593,#594));
#596=FACE_BOUND('',#595,.T.);
#597=ADVANCED_FACE('F885',(#596),#569,.T.);
#598=CARTESIAN_POINT('',(-17.6403,22.7584,12.7));
#599=DIRECTION('',(0.,-1.,0.));
#600=DIRECTION('',(1.,0.,0.));
#601=AXIS2_PLACEMENT_3D('',#598,#599,#600);
#602=PLANE('',#601);
#603=DIRECTION('',(-1.,0.,0.));
#604=VECTOR('',#603,1.);
#605=CARTESIAN_POINT('',(-17.6403,22.7584,-12.7));
#606=LINE('',#605,#604);
#607=CARTESIAN_POINT('',(-17.6403,22.7584,-12.7));
#608=VERTEX_POINT('',#607);
#609=EDGE_CURVE('E454',#576,#608,#606,.T.);
#610=ORIENTED_EDGE('',*,*,#609,.T.);
#611=DIRECTION('',(0.,0.,-1.));
#612=VECTOR('',#611,1.);
#613=CARTESIAN_POINT('',(-17.6403,22.7584,12.7));
#614=LINE('',#613,#612);
#615=CARTESIAN_POINT('',(-17.6403,22.7584,12.7));
#616=VERTEX_POINT('',#615);
#617=EDGE_CURVE('E630',#616,#608,#614,.T.);
#618=ORIENTED_EDGE('',*,*,#617,.F.);
#619=DIRECTION('',(-1.,0.,0.));
#620=VECTOR('',#619,1.);
#621=CARTESIAN_POINT('',(-17.6403,22.7584,12.7));
#622=LINE('',#621,#620);
#623=EDGE_CURVE('E734',#584,#616,#622,.T.);
#624=ORIENTED_EDGE('',*,*,#623,.F.);
#625=ORIENTED_EDGE('',*,*,#585,.T.);
#626=EDGE_LOOP('',(#610,#618,#624,#625));
#627=FACE_BOUND('',#626,.T.);
#628=ADVANCED_FACE('F889',(#627),#602,.F.);
#629=CARTESIAN_POINT('',(-17.6403,19.1676263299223,12.7));
#630=DIRECTION('',(0.,0.,-1.));
#631=DIRECTION('',(-1.,0.,0.));
#632=AXIS2_PLACEMENT_3D('',#629,#630,#631);
#633=CYLINDRICAL_SURFACE('',#632,3.59077367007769);
#634=CARTESIAN_POINT('',(-17.6403,19.1676263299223,-12.7));
#635=DIRECTION('',(0.,0.,1.));
#636=DIRECTION('',(1.,0.,0.));
#637=AXIS2_PLACEMENT_3D('',#634,#635,#636);
#638=CIRCLE('',#637,3.59077367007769);
#639=CARTESIAN_POINT('',(-21.1624286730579,18.4688666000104,-12.7));
#640=VERTEX_POINT('',#639);
#641=EDGE_CURVE('E456',#608,#640,#638,.T.);
#642=ORIENTED_EDGE('',*,*,#641,.T.);
#643=DIRECTION('',(0.,0.,-1.));
#644=VECTOR('',#643,1.);
#645=CARTESIAN_POINT('',(-21.1624286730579,18.4688666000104,12.7));
#646=LINE('',#645,#644);
#647=CARTESIAN_POINT('',(-21.1624286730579,18.4688666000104,12.7));
#648=VERTEX_POINT('',#647);
#649=EDGE_CURVE('E627',#648,#640,#646,.T.);
#650=ORIENTED_EDGE('',*,*,#649,.F.);
#651=CARTESIAN_POINT('',(-17.6403,19.1676263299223,12.7));
#652=DIRECTION('',(0.,0.,1.));
#653=DIRECTION('',(1.,0.,0.));
#654=AXIS2_PLACEMENT_3D('',#651,#652,#653);
#655=CIRCLE('',#654,3.59077367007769);
#656=EDGE_CURVE('E736',#616,#648,#655,.T.);
#657=ORIENTED_EDGE('',*,*,#656,.F.);
#658=ORIENTED_EDGE('',*,*,#617,.T.);
#659=EDGE_LOOP('',(#642,#650,#657,#658));
#660=FACE_BOUND('',#659,.T.);
#661=ADVANCED_FACE('F893',(#660),#633,.T.);
#662=CARTESIAN_POINT('',(-19.1389,15.8307359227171,12.7));
#663=DIRECTION('',(0.793466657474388,0.608613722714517,0.));
#664=DIRECTION('',(-0.608613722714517,0.793466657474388,0.));
#665=AXIS2_PLACEMENT_3D('',#662,#663,#664);
#666=PLANE('',#665);
#667=DIRECTION('',(0.608613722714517,-0.793466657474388,0.));
#668=VECTOR('',#667,1.);
#669=CARTESIAN_POINT('',(-19.1389,15.8307359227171,-12.7));
#670=LINE('',#669,#668);
#671=CARTESIAN_POINT('',(-19.1389,15.8307359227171,-12.7));
#672=VERTEX_POINT('',#671);
#673=EDGE_CURVE('E458',#640,#672,#670,.T.);
#674=ORIENTED_EDGE('',*,*,#673,.T.);
#675=DIRECTION('',(0.,0.,-1.));
#676=VECTOR('',#675,1.);
#677=CARTESIAN_POINT('',(-19.1389,15.8307359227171,12.7));
#678=LINE('',#677,#676);
#679=CARTESIAN_POINT('',(-19.1389,15.8307359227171,12.7));
#680=VERTEX_POINT('',#679);
#681=EDGE_CURVE('E624',#680,#672,#678,.T.);
#682=ORIENTED_EDGE('',*,*,#681,.F.);
#683=DIRECTION('',(0.608613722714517,-0.793466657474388,0.));
#684=VECTOR('',#683,1.);
#685=CARTESIAN_POINT('',(-19.1389,15.8307359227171,12.7));
#686=LINE('',#685,#684);
#687=EDGE_CURVE('E738',#648,#680,#686,.T.);
#688=ORIENTED_EDGE('',*,*,#687,.F.);
#689=ORIENTED_EDGE('',*,*,#649,.T.);
#690=EDGE_LOOP('',(#674,#682,#688,#689));
#691=FACE_BOUND('',#690,.T.);
#692=ADVANCED_FACE('F897',(#691),#666,.F.);
#693=CARTESIAN_POINT('',(-19.1389,10.7491294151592,12.7));
#694=DIRECTION('',(1.,0.,0.));
#695=DIRECTION('',(0.,0.,-1.));
#696=AXIS2_PLACEMENT_3D('',#693,#694,#695);
#697=PLANE('',#696);
#698=DIRECTION('',(0.,-1.,0.));
#699=VECTOR('',#698,1.);
#700=CARTESIAN_POINT('',(-19.1389,10.7491294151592,-12.7));
#701=LINE('',#700,#699);
#702=CARTESIAN_POINT('',(-19.1389,10.7491294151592,-12.7));
#703=VERTEX_POINT('',#702);
#704=EDGE_CURVE('E460',#672,#703,#701,.T.);
#705=ORIENTED_EDGE('',*,*,#704,.T.);
#706=DIRECTION('',(0.,0.,-1.));
#707=VECTOR('',#706,1.);
#708=CARTESIAN_POINT('',(-19.1389,10.7491294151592,12.7));
#709=LINE('',#708,#707);
#710=CARTESIAN_POINT('',(-19.1389,10.7491294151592,12.7));
#711=VERTEX_POINT('',#710);
#712=EDGE_CURVE('E621',#711,#703,#709,.T.);
#713=ORIENTED_EDGE('',*,*,#712,.F.);
#714=DIRECTION('',(0.,-1.,0.));
#715=VECTOR('',#714,1.);
#716=CARTESIAN_POINT('',(-19.1389,10.7491294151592,12.7));
#717=LINE('',#716,#715);
#718=EDGE_CURVE('E740',#680,#711,#717,.T.);
#719=ORIENTED_EDGE('',*,*,#718,.F.);
#720=ORIENTED_EDGE('',*,*,#681,.T.);
#721=EDGE_LOOP('',(#705,#713,#719,#720));
#722=FACE_BOUND('',#721,.T.);
#723=ADVANCED_FACE('F901',(#722),#697,.F.);
#724=CARTESIAN_POINT('',(-19.1389,10.7491294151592,12.7));
#725=DIRECTION('',(0.746819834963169,-0.665026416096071,0.));
#726=DIRECTION('',(0.665026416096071,0.746819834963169,0.));
#727=AXIS2_PLACEMENT_3D('',#724,#725,#726);
#728=PLANE('',#727);
#729=DIRECTION('',(-0.665026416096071,-0.746819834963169,0.));
#730=VECTOR('',#729,1.);
#731=CARTESIAN_POINT('',(-19.1389,10.7491294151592,-12.7));
#732=LINE('',#731,#730);
#733=CARTESIAN_POINT('',(-20.6375,9.0662125,-12.7));
#734=VERTEX_POINT('',#733);
#735=EDGE_CURVE('E462',#703,#734,#732,.T.);
#736=ORIENTED_EDGE('',*,*,#735,.T.);
#737=DIRECTION('',(0.,0.,-1.));
#738=VECTOR('',#737,1.);
#739=CARTESIAN_POINT('',(-20.6375,9.0662125,12.7));
#740=LINE('',#739,#738);
#741=CARTESIAN_POINT('',(-20.6375,9.0662125,12.7));
#742=VERTEX_POINT('',#741);
#743=EDGE_CURVE('E618',#742,#734,#740,.T.);
#744=ORIENTED_EDGE('',*,*,#743,.F.);
#745=DIRECTION('',(-0.665026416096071,-0.746819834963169,0.));
#746=VECTOR('',#745,1.);
#747=CARTESIAN_POINT('',(-19.1389,10.7491294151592,12.7));
#748=LINE('',#747,#746);
#749=EDGE_CURVE('E742',#711,#742,#748,.T.);
#750=ORIENTED_EDGE('',*,*,#749,.F.);
#751=ORIENTED_EDGE('',*,*,#712,.T.);
#752=EDGE_LOOP('',(#736,#744,#750,#751));
#753=FACE_BOUND('',#752,.T.);
#754=ADVANCED_FACE('F905',(#753),#728,.F.);
#755=CARTESIAN_POINT('',(-20.6375,-4.8244125,12.7));
#756=DIRECTION('',(1.,0.,0.));
#757=DIRECTION('',(0.,1.,0.));
#758=AXIS2_PLACEMENT_3D('',#755,#756,#757);
#759=PLANE('',#758);
#760=DIRECTION('',(0.,-1.,0.));
#761=VECTOR('',#760,1.);
#762=CARTESIAN_POINT('',(-20.6375,-4.8244125,-12.7));
#763=LINE('',#762,#761);
#764=CARTESIAN_POINT('',(-20.6375,-4.8244125,-12.7));
#765=VERTEX_POINT('',#764);
#766=EDGE_CURVE('E464',#734,#765,#763,.T.);
#767=ORIENTED_EDGE('',*,*,#766,.T.);
#768=DIRECTION('',(0.,0.,-1.));
#769=VECTOR('',#768,1.);
#770=CARTESIAN_POINT('',(-20.6375,-4.8244125,12.7));
#771=LINE('',#770,#769);
#772=CARTESIAN_POINT('',(-20.6375,-4.8244125,12.7));
#773=VERTEX_POINT('',#772);
#774=EDGE_CURVE('E615',#773,#765,#771,.T.);
#775=ORIENTED_EDGE('',*,*,#774,.F.);
#776=DIRECTION('',(0.,-1.,0.));
#777=VECTOR('',#776,1.);
#778=CARTESIAN_POINT('',(-20.6375,-4.8244125,12.7));
#779=LINE('',#778,#777);
#780=EDGE_CURVE('E744',#742,#773,#779,.T.);
#781=ORIENTED_EDGE('',*,*,#780,.F.);
#782=ORIENTED_EDGE('',*,*,#743,.T.);
#783=EDGE_LOOP('',(#767,#775,#781,#782));
#784=FACE_BOUND('',#783,.T.);
#785=ADVANCED_FACE('F909',(#784),#759,.F.);
#786=CARTESIAN_POINT('',(-19.1389,-6.50732941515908,12.7));
#787=DIRECTION('',(0.746819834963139,0.665026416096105,0.));
#788=DIRECTION('',(-0.665026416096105,0.746819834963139,0.));
#789=AXIS2_PLACEMENT_3D('',#786,#787,#788);
#790=PLANE('',#789);
#791=DIRECTION('',(0.665026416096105,-0.746819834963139,0.));
#792=VECTOR('',#791,1.);
#793=CARTESIAN_POINT('',(-19.1389,-6.50732941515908,-12.7));
#794=LINE('',#793,#792);
#795=CARTESIAN_POINT('',(-19.1389,-6.50732941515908,-12.7));
#796=VERTEX_POINT('',#795);
#797=EDGE_CURVE('E466',#765,#796,#794,.T.);
#798=ORIENTED_EDGE('',*,*,#797,.T.);
#799=DIRECTION('',(0.,0.,-1.));
#800=VECTOR('',#799,1.);
#801=CARTESIAN_POINT('',(-19.1389,-6.50732941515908,12.7));
#802=LINE('',#801,#800);
#803=CARTESIAN_POINT('',(-19.1389,-6.50732941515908,12.7));
#804=VERTEX_POINT('',#803);
#805=EDGE_CURVE('E612',#804,#796,#802,.T.);
#806=ORIENTED_EDGE('',*,*,#805,.F.);
#807=DIRECTION('',(0.665026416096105,-0.746819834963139,0.));
#808=VECTOR('',#807,1.);
#809=CARTESIAN_POINT('',(-19.1389,-6.50732941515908,12.7));
#810=LINE('',#809,#808);
#811=EDGE_CURVE('E746',#773,#804,#810,.T.);
#812=ORIENTED_EDGE('',*,*,#811,.F.);
#813=ORIENTED_EDGE('',*,*,#774,.T.);
#814=EDGE_LOOP('',(#798,#806,#812,#813));
#815=FACE_BOUND('',#814,.T.);
#816=ADVANCED_FACE('F913',(#815),#790,.F.);
#817=CARTESIAN_POINT('',(-19.1389,-13.3587845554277,12.7));
#818=DIRECTION('',(1.,0.,0.));
#819=DIRECTION('',(0.,0.,-1.));
#820=AXIS2_PLACEMENT_3D('',#817,#818,#819);
#821=PLANE('',#820);
#822=DIRECTION('',(0.,-1.,0.));
#823=VECTOR('',#822,1.);
#824=CARTESIAN_POINT('',(-19.1389,-13.3587845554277,-12.7));
#825=LINE('',#824,#823);
#826=CARTESIAN_POINT('',(-19.1389,-13.3587845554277,-12.7));
#827=VERTEX_POINT('',#826);
#828=EDGE_CURVE('E468',#796,#827,#825,.T.);
#829=ORIENTED_EDGE('',*,*,#828,.T.);
#830=DIRECTION('',(0.,0.,-1.));
#831=VECTOR('',#830,1.);
#832=CARTESIAN_POINT('',(-19.1389,-13.3587845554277,12.7));
#833=LINE('',#832,#831);
#834=CARTESIAN_POINT('',(-19.1389,-13.3587845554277,12.7));
#835=VERTEX_POINT('',#834);
#836=EDGE_CURVE('E609',#835,#827,#833,.T.);
#837=ORIENTED_EDGE('',*,*,#836,.F.);
#838=DIRECTION('',(0.,-1.,0.));
#839=VECTOR('',#838,1.);
#840=CARTESIAN_POINT('',(-19.1389,-13.3587845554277,12.7));
#841=LINE('',#840,#839);
#842=EDGE_CURVE('E748',#804,#835,#841,.T.);
#843=ORIENTED_EDGE('',*,*,#842,.F.);
#844=ORIENTED_EDGE('',*,*,#805,.T.);
#845=EDGE_LOOP('',(#829,#837,#843,#844));
#846=FACE_BOUND('',#845,.T.);
#847=ADVANCED_FACE('F917',(#846),#821,.F.);
#848=CARTESIAN_POINT('',(-19.1389,-13.3587845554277,12.7));
#849=DIRECTION('',(0.707106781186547,-0.707106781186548,0.));
#850=DIRECTION('',(0.707106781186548,0.707106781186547,0.));
#851=AXIS2_PLACEMENT_3D('',#848,#849,#850);
#852=PLANE('',#851);
#853=DIRECTION('',(-0.707106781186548,-0.707106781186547,0.));
#854=VECTOR('',#853,1.);
#855=CARTESIAN_POINT('',(-19.1389,-13.3587845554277,-12.7));
#856=LINE('',#855,#854);
#857=CARTESIAN_POINT('',(-20.5534580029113,-14.773342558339,-12.7));
#858=VERTEX_POINT('',#857);
#859=EDGE_CURVE('E470',#827,#858,#856,.T.);
#860=ORIENTED_EDGE('',*,*,#859,.T.);
#861=DIRECTION('',(0.,0.,-1.));
#862=VECTOR('',#861,1.);
#863=CARTESIAN_POINT('',(-20.5534580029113,-14.773342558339,12.7));
#864=LINE('',#863,#862);
#865=CARTESIAN_POINT('',(-20.5534580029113,-14.773342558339,12.7));
#866=VERTEX_POINT('',#865);
#867=EDGE_CURVE('E606',#866,#858,#864,.T.);
#868=ORIENTED_EDGE('',*,*,#867,.F.);
#869=DIRECTION('',(-0.707106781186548,-0.707106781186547,0.));
#870=VECTOR('',#869,1.);
#871=CARTESIAN_POINT('',(-19.1389,-13.3587845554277,12.7));
#872=LINE('',#871,#870);
#873=EDGE_CURVE('E750',#835,#866,#872,.T.);
#874=ORIENTED_EDGE('',*,*,#873,.F.);
#875=ORIENTED_EDGE('',*,*,#836,.T.);
#876=EDGE_LOOP('',(#860,#868,#874,#875));
#877=FACE_BOUND('',#876,.T.);
#878=ADVANCED_FACE('F921',(#877),#852,.F.);
#879=CARTESIAN_POINT('',(-17.6403,-15.478125,12.7));
#880=DIRECTION('',(0.,0.,-1.));
#881=DIRECTION('',(-1.,0.,0.));
#882=AXIS2_PLACEMENT_3D('',#879,#880,#881);
#883=CYLINDRICAL_SURFACE('',#882,2.9972);
#884=CARTESIAN_POINT('',(-17.6403,-15.478125,-12.7));
#885=DIRECTION('',(0.,0.,1.));
#886=DIRECTION('',(1.,0.,0.));
#887=AXIS2_PLACEMENT_3D('',#884,#885,#886);
#888=CIRCLE('',#887,2.9972);
#889=CARTESIAN_POINT('',(-15.019825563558,-16.9328832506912,-12.7));
#890=VERTEX_POINT('',#889);
#891=EDGE_CURVE('E472',#858,#890,#888,.T.);
#892=ORIENTED_EDGE('',*,*,#891,.T.);
#893=DIRECTION('',(0.,0.,-1.));
#894=VECTOR('',#893,1.);
#895=CARTESIAN_POINT('',(-15.019825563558,-16.9328832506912,12.7));
#896=LINE('',#895,#894);
#897=CARTESIAN_POINT('',(-15.019825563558,-16.9328832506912,12.7));
#898=VERTEX_POINT('',#897);
#899=EDGE_CURVE('E603',#898,#890,#896,.T.);
#900=ORIENTED_EDGE('',*,*,#899,.F.);
#901=CARTESIAN_POINT('',(-17.6403,-15.478125,12.7));
#902=DIRECTION('',(0.,0.,1.));
#903=DIRECTION('',(1.,0.,0.));
#904=AXIS2_PLACEMENT_3D('',#901,#902,#903);
#905=CIRCLE('',#904,2.9972);
#906=EDGE_CURVE('E752',#866,#898,#905,.T.);
#907=ORIENTED_EDGE('',*,*,#906,.F.);
#908=ORIENTED_EDGE('',*,*,#867,.T.);
#909=EDGE_LOOP('',(#892,#900,#907,#908));
#910=FACE_BOUND('',#909,.T.);
#911=ADVANCED_FACE('F925',(#910),#883,.T.);
#912=CARTESIAN_POINT('',(-13.7938113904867,-17.794678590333,12.7));
#913=DIRECTION('',(0.,0.,-1.));
#914=DIRECTION('',(-1.,0.,0.));
#915=AXIS2_PLACEMENT_3D('',#912,#913,#914);
#916=CYLINDRICAL_SURFACE('',#915,1.4986);
#917=CARTESIAN_POINT('',(-13.7938113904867,-17.794678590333,-12.7));
#918=DIRECTION('',(0.,0.,-1.));
#919=DIRECTION('',(-1.,0.,0.));
#920=AXIS2_PLACEMENT_3D('',#917,#918,#919);
#921=CIRCLE('',#920,1.4986);
#922=CARTESIAN_POINT('',(-12.4805591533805,-18.5166,-12.7));
#923=VERTEX_POINT('',#922);
#924=EDGE_CURVE('E474',#890,#923,#921,.T.);
#925=ORIENTED_EDGE('',*,*,#924,.T.);
#926=DIRECTION('',(0.,0.,-1.));
#927=VECTOR('',#926,1.);
#928=CARTESIAN_POINT('',(-12.4805591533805,-18.5166,12.7));
#929=LINE('',#928,#927);
#930=CARTESIAN_POINT('',(-12.4805591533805,-18.5166,12.7));
#931=VERTEX_POINT('',#930);
#932=EDGE_CURVE('E600',#931,#923,#929,.T.);
#933=ORIENTED_EDGE('',*,*,#932,.F.);
#934=CARTESIAN_POINT('',(-13.7938113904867,-17.794678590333,12.7));
#935=DIRECTION('',(0.,0.,-1.));
#936=DIRECTION('',(-1.,0.,0.));
#937=AXIS2_PLACEMENT_3D('',#934,#935,#936);
#938=CIRCLE('',#937,1.4986);
#939=EDGE_CURVE('E754',#898,#931,#938,.T.);
#940=ORIENTED_EDGE('',*,*,#939,.F.);
#941=ORIENTED_EDGE('',*,*,#899,.T.);
#942=EDGE_LOOP('',(#925,#933,#940,#941));
#943=FACE_BOUND('',#942,.T.);
#944=ADVANCED_FACE('F929',(#943),#916,.F.);
#945=CARTESIAN_POINT('',(-12.4805591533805,-18.5166,12.7));
#946=DIRECTION('',(0.,1.,0.));
#947=DIRECTION('',(0.,0.,1.));
#948=AXIS2_PLACEMENT_3D('',#945,#946,#947);
#949=PLANE('',#948);
#950=DIRECTION('',(1.,0.,0.));
#951=VECTOR('',#950,1.);
#952=CARTESIAN_POINT('',(-12.4805591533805,-18.5166,-12.7));
#953=LINE('',#952,#951);
#954=CARTESIAN_POINT('',(12.4805591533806,-18.5166,-12.7));
#955=VERTEX_POINT('',#954);
#956=EDGE_CURVE('E476',#923,#955,#953,.T.);
#957=ORIENTED_EDGE('',*,*,#956,.T.);
#958=DIRECTION('',(0.,0.,-1.));
#959=VECTOR('',#958,1.);
#960=CARTESIAN_POINT('',(12.4805591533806,-18.5166,12.7));
#961=LINE('',#960,#959);
#962=CARTESIAN_POINT('',(12.4805591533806,-18.5166,12.7));
#963=VERTEX_POINT('',#962);
#964=EDGE_CURVE('E597',#963,#955,#961,.T.);
#965=ORIENTED_EDGE('',*,*,#964,.F.);
#966=DIRECTION('',(1.,0.,0.));
#967=VECTOR('',#966,1.);
#968=CARTESIAN_POINT('',(-12.4805591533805,-18.5166,12.7));
#969=LINE('',#968,#967);
#970=EDGE_CURVE('E756',#931,#963,#969,.T.);
#971=ORIENTED_EDGE('',*,*,#970,.F.);
#972=ORIENTED_EDGE('',*,*,#932,.T.);
#973=EDGE_LOOP('',(#957,#965,#971,#972));
#974=FACE_BOUND('',#973,.T.);
#975=ADVANCED_FACE('F933',(#974),#949,.F.);
#976=CARTESIAN_POINT('',(13.7938113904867,-17.794678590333,12.7));
#977=DIRECTION('',(0.,0.,-1.));
#978=DIRECTION('',(-1.,0.,0.));
#979=AXIS2_PLACEMENT_3D('',#976,#977,#978);
#980=CYLINDRICAL_SURFACE('',#979,1.4986);
#981=CARTESIAN_POINT('',(13.7938113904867,-17.794678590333,-12.7));
#982=DIRECTION('',(0.,0.,-1.));
#983=DIRECTION('',(1.,0.,0.));
#984=AXIS2_PLACEMENT_3D('',#981,#982,#983);
#985=CIRCLE('',#984,1.4986);
#986=CARTESIAN_POINT('',(15.0198255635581,-16.9328832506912,-12.7));
#987=VERTEX_POINT('',#986);
#988=EDGE_CURVE('E478',#955,#987,#985,.T.);
#989=ORIENTED_EDGE('',*,*,#988,.T.);
#990=DIRECTION('',(0.,0.,-1.));
#991=VECTOR('',#990,1.);
#992=CARTESIAN_POINT('',(15.0198255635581,-16.9328832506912,12.7));
#993=LINE('',#992,#991);
#994=CARTESIAN_POINT('',(15.0198255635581,-16.9328832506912,12.7));
#995=VERTEX_POINT('',#994);
#996=EDGE_CURVE('E594',#995,#987,#993,.T.);
#997=ORIENTED_EDGE('',*,*,#996,.F.);
#998=CARTESIAN_POINT('',(13.7938113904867,-17.794678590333,12.7));
#999=DIRECTION('',(0.,0.,-1.));
#1000=DIRECTION('',(1.,0.,0.));
#1001=AXIS2_PLACEMENT_3D('',#998,#999,#1000);
#1002=CIRCLE('',#1001,1.4986);
#1003=EDGE_CURVE('E758',#963,#995,#1002,.T.);
#1004=ORIENTED_EDGE('',*,*,#1003,.F.);
#1005=ORIENTED_EDGE('',*,*,#964,.T.);
#1006=EDGE_LOOP('',(#989,#997,#1004,#1005));
#1007=FACE_BOUND('',#1006,.T.);
#1008=ADVANCED_FACE('F937',(#1007),#980,.F.);
#1009=CARTESIAN_POINT('',(17.6403,-15.478125,12.7));
#1010=DIRECTION('',(0.,0.,-1.));
#1011=DIRECTION('',(-1.,0.,0.));
#1012=AXIS2_PLACEMENT_3D('',#1009,#1010,#1011);
#1013=CYLINDRICAL_SURFACE('',#1012,2.9972);
#1014=CARTESIAN_POINT('',(17.6403,-15.478125,-12.7));
#1015=DIRECTION('',(0.,0.,1.));
#1016=DIRECTION('',(-1.,0.,0.));
#1017=AXIS2_PLACEMENT_3D('',#1014,#1015,#1016);
#1018=CIRCLE('',#1017,2.9972);
#1019=CARTESIAN_POINT('',(20.5534580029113,-14.773342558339,-12.7));
#1020=VERTEX_POINT('',#1019);
#1021=EDGE_CURVE('E480',#987,#1020,#1018,.T.);
#1022=ORIENTED_EDGE('',*,*,#1021,.T.);
#1023=DIRECTION('',(0.,0.,-1.));
#1024=VECTOR('',#1023,1.);
#1025=CARTESIAN_POINT('',(20.5534580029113,-14.773342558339,12.7));
#1026=LINE('',#1025,#1024);
#1027=CARTESIAN_POINT('',(20.5534580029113,-14.773342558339,12.7));
#1028=VERTEX_POINT('',#1027);
#1029=EDGE_CURVE('E591',#1028,#1020,#1026,.T.);
#1030=ORIENTED_EDGE('',*,*,#1029,.F.);
#1031=CARTESIAN_POINT('',(17.6403,-15.478125,12.7));
#1032=DIRECTION('',(0.,0.,1.));
#1033=DIRECTION('',(-1.,0.,0.));
#1034=AXIS2_PLACEMENT_3D('',#1031,#1032,#1033);
#1035=CIRCLE('',#1034,2.9972);
#1036=EDGE_CURVE('E760',#995,#1028,#1035,.T.);
#1037=ORIENTED_EDGE('',*,*,#1036,.F.);
#1038=ORIENTED_EDGE('',*,*,#996,.T.);
#1039=EDGE_LOOP('',(#1022,#1030,#1037,#1038));
#1040=FACE_BOUND('',#1039,.T.);
#1041=ADVANCED_FACE('F941',(#1040),#1013,.T.);
#1042=CARTESIAN_POINT('',(19.1389,-13.3587845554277,12.7));
#1043=DIRECTION('',(-0.707106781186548,-0.707106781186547,0.));
#1044=DIRECTION('',(0.707106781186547,-0.707106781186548,0.));
#1045=AXIS2_PLACEMENT_3D('',#1042,#1043,#1044);
#1046=PLANE('',#1045);
#1047=DIRECTION('',(-0.707106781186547,0.707106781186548,0.));
#1048=VECTOR('',#1047,1.);
#1049=CARTESIAN_POINT('',(19.1389,-13.3587845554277,-12.7));
#1050=LINE('',#1049,#1048);
#1051=CARTESIAN_POINT('',(19.1389,-13.3587845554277,-12.7));
#1052=VERTEX_POINT('',#1051);
#1053=EDGE_CURVE('E482',#1020,#1052,#1050,.T.);
#1054=ORIENTED_EDGE('',*,*,#1053,.T.);
#1055=DIRECTION('',(0.,0.,-1.));
#1056=VECTOR('',#1055,1.);
#1057=CARTESIAN_POINT('',(19.1389,-13.3587845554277,12.7));
#1058=LINE('',#1057,#1056);
#1059=CARTESIAN_POINT('',(19.1389,-13.3587845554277,12.7));
#1060=VERTEX_POINT('',#1059);
#1061=EDGE_CURVE('E588',#1060,#1052,#1058,.T.);
#1062=ORIENTED_EDGE('',*,*,#1061,.F.);
#1063=DIRECTION('',(-0.707106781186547,0.707106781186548,0.));
#1064=VECTOR('',#1063,1.);
#1065=CARTESIAN_POINT('',(19.1389,-13.3587845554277,12.7));
#1066=LINE('',#1065,#1064);
#1067=EDGE_CURVE('E762',#1028,#1060,#1066,.T.);
#1068=ORIENTED_EDGE('',*,*,#1067,.F.);
#1069=ORIENTED_EDGE('',*,*,#1029,.T.);
#1070=EDGE_LOOP('',(#1054,#1062,#1068,#1069));
#1071=FACE_BOUND('',#1070,.T.);
#1072=ADVANCED_FACE('F945',(#1071),#1046,.F.);
#1073=CARTESIAN_POINT('',(19.1389,-13.3587845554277,12.7));
#1074=DIRECTION('',(-1.,0.,0.));
#1075=DIRECTION('',(0.,-1.,0.));
#1076=AXIS2_PLACEMENT_3D('',#1073,#1074,#1075);
#1077=PLANE('',#1076);
#1078=DIRECTION('',(0.,1.,0.));
#1079=VECTOR('',#1078,1.);
#1080=CARTESIAN_POINT('',(19.1389,-13.3587845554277,-12.7));
#1081=LINE('',#1080,#1079);
#1082=CARTESIAN_POINT('',(19.1389,-6.50732941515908,-12.7));
#1083=VERTEX_POINT('',#1082);
#1084=EDGE_CURVE('E484',#1052,#1083,#1081,.T.);
#1085=ORIENTED_EDGE('',*,*,#1084,.T.);
#1086=DIRECTION('',(0.,0.,-1.));
#1087=VECTOR('',#1086,1.);
#1088=CARTESIAN_POINT('',(19.1389,-6.50732941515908,12.7));
#1089=LINE('',#1088,#1087);
#1090=CARTESIAN_POINT('',(19.1389,-6.50732941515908,12.7));
#1091=VERTEX_POINT('',#1090);
#1092=EDGE_CURVE('E585',#1091,#1083,#1089,.T.);
#1093=ORIENTED_EDGE('',*,*,#1092,.F.);
#1094=DIRECTION('',(0.,1.,0.));
#1095=VECTOR('',#1094,1.);
#1096=CARTESIAN_POINT('',(19.1389,-13.3587845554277,12.7));
#1097=LINE('',#1096,#1095);
#1098=EDGE_CURVE('E764',#1060,#1091,#1097,.T.);
#1099=ORIENTED_EDGE('',*,*,#1098,.F.);
#1100=ORIENTED_EDGE('',*,*,#1061,.T.);
#1101=EDGE_LOOP('',(#1085,#1093,#1099,#1100));
#1102=FACE_BOUND('',#1101,.T.);
#1103=ADVANCED_FACE('F949',(#1102),#1077,.F.);
#1104=CARTESIAN_POINT('',(19.1389,-6.50732941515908,12.7));
#1105=DIRECTION('',(-0.746819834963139,0.665026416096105,0.));
#1106=DIRECTION('',(-0.665026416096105,-0.746819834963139,0.));
#1107=AXIS2_PLACEMENT_3D('',#1104,#1105,#1106);
#1108=PLANE('',#1107);
#1109=DIRECTION('',(0.665026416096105,0.746819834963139,0.));
#1110=VECTOR('',#1109,1.);
#1111=CARTESIAN_POINT('',(19.1389,-6.50732941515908,-12.7));
#1112=LINE('',#1111,#1110);
#1113=CARTESIAN_POINT('',(20.6375,-4.82441249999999,-12.7));
#1114=VERTEX_POINT('',#1113);
#1115=EDGE_CURVE('E486',#1083,#1114,#1112,.T.);
#1116=ORIENTED_EDGE('',*,*,#1115,.T.);
#1117=DIRECTION('',(0.,0.,-1.));
#1118=VECTOR('',#1117,1.);
#1119=CARTESIAN_POINT('',(20.6375,-4.82441249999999,12.7));
#1120=LINE('',#1119,#1118);
#1121=CARTESIAN_POINT('',(20.6375,-4.82441249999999,12.7));
#1122=VERTEX_POINT('',#1121);
#1123=EDGE_CURVE('E582',#1122,#1114,#1120,.T.);
#1124=ORIENTED_EDGE('',*,*,#1123,.F.);
#1125=DIRECTION('',(0.665026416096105,0.746819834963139,0.));
#1126=VECTOR('',#1125,1.);
#1127=CARTESIAN_POINT('',(19.1389,-6.50732941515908,12.7));
#1128=LINE('',#1127,#1126);
#1129=EDGE_CURVE('E766',#1091,#1122,#1128,.T.);
#1130=ORIENTED_EDGE('',*,*,#1129,.F.);
#1131=ORIENTED_EDGE('',*,*,#1092,.T.);
#1132=EDGE_LOOP('',(#1116,#1124,#1130,#1131));
#1133=FACE_BOUND('',#1132,.T.);
#1134=ADVANCED_FACE('F953',(#1133),#1108,.F.);
#1135=CARTESIAN_POINT('',(20.6375,-4.82441249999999,12.7));
#1136=DIRECTION('',(-1.,0.,0.));
#1137=DIRECTION('',(0.,-1.,0.));
#1138=AXIS2_PLACEMENT_3D('',#1135,#1136,#1137);
#1139=PLANE('',#1138);
#1140=DIRECTION('',(0.,1.,0.));
#1141=VECTOR('',#1140,1.);
#1142=CARTESIAN_POINT('',(20.6375,-4.82441249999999,-12.7));
#1143=LINE('',#1142,#1141);
#1144=CARTESIAN_POINT('',(20.6375,9.06621250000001,-12.7));
#1145=VERTEX_POINT('',#1144);
#1146=EDGE_CURVE('E488',#1114,#1145,#1143,.T.);
#1147=ORIENTED_EDGE('',*,*,#1146,.T.);
#1148=DIRECTION('',(0.,0.,-1.));
#1149=VECTOR('',#1148,1.);
#1150=CARTESIAN_POINT('',(20.6375,9.06621250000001,12.7));
#1151=LINE('',#1150,#1149);
#1152=CARTESIAN_POINT('',(20.6375,9.06621250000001,12.7));
#1153=VERTEX_POINT('',#1152);
#1154=EDGE_CURVE('E579',#1153,#1145,#1151,.T.);
#1155=ORIENTED_EDGE('',*,*,#1154,.F.);
#1156=DIRECTION('',(0.,1.,0.));
#1157=VECTOR('',#1156,1.);
#1158=CARTESIAN_POINT('',(20.6375,-4.82441249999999,12.7));
#1159=LINE('',#1158,#1157);
#1160=EDGE_CURVE('E768',#1122,#1153,#1159,.T.);
#1161=ORIENTED_EDGE('',*,*,#1160,.F.);
#1162=ORIENTED_EDGE('',*,*,#1123,.T.);
#1163=EDGE_LOOP('',(#1147,#1155,#1161,#1162));
#1164=FACE_BOUND('',#1163,.T.);
#1165=ADVANCED_FACE('F957',(#1164),#1139,.F.);
#1166=CARTESIAN_POINT('',(19.1389,10.7491294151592,12.7));
#1167=DIRECTION('',(-0.746819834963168,-0.665026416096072,0.));
#1168=DIRECTION('',(0.665026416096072,-0.746819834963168,0.));
#1169=AXIS2_PLACEMENT_3D('',#1166,#1167,#1168);
#1170=PLANE('',#1169);
#1171=DIRECTION('',(-0.665026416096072,0.746819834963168,0.));
#1172=VECTOR('',#1171,1.);
#1173=CARTESIAN_POINT('',(19.1389,10.7491294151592,-12.7));
#1174=LINE('',#1173,#1172);
#1175=CARTESIAN_POINT('',(19.1389,10.7491294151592,-12.7));
#1176=VERTEX_POINT('',#1175);
#1177=EDGE_CURVE('E490',#1145,#1176,#1174,.T.);
#1178=ORIENTED_EDGE('',*,*,#1177,.T.);
#1179=DIRECTION('',(0.,0.,-1.));
#1180=VECTOR('',#1179,1.);
#1181=CARTESIAN_POINT('',(19.1389,10.7491294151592,12.7));
#1182=LINE('',#1181,#1180);
#1183=CARTESIAN_POINT('',(19.1389,10.7491294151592,12.7));
#1184=VERTEX_POINT('',#1183);
#1185=EDGE_CURVE('E576',#1184,#1176,#1182,.T.);
#1186=ORIENTED_EDGE('',*,*,#1185,.F.);
#1187=DIRECTION('',(-0.665026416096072,0.746819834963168,0.));
#1188=VECTOR('',#1187,1.);
#1189=CARTESIAN_POINT('',(19.1389,10.7491294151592,12.7));
#1190=LINE('',#1189,#1188);
#1191=EDGE_CURVE('E770',#1153,#1184,#1190,.T.);
#1192=ORIENTED_EDGE('',*,*,#1191,.F.);
#1193=ORIENTED_EDGE('',*,*,#1154,.T.);
#1194=EDGE_LOOP('',(#1178,#1186,#1192,#1193));
#1195=FACE_BOUND('',#1194,.T.);
#1196=ADVANCED_FACE('F961',(#1195),#1170,.F.);
#1197=CARTESIAN_POINT('',(19.1389,10.7491294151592,12.7));
#1198=DIRECTION('',(-1.,0.,0.));
#1199=DIRECTION('',(0.,-1.,0.));
#1200=AXIS2_PLACEMENT_3D('',#1197,#1198,#1199);
#1201=PLANE('',#1200);
#1202=DIRECTION('',(0.,1.,0.));
#1203=VECTOR('',#1202,1.);
#1204=CARTESIAN_POINT('',(19.1389,10.7491294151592,-12.7));
#1205=LINE('',#1204,#1203);
#1206=CARTESIAN_POINT('',(19.1389,15.8307359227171,-12.7));
#1207=VERTEX_POINT('',#1206);
#1208=EDGE_CURVE('E492',#1176,#1207,#1205,.T.);
#1209=ORIENTED_EDGE('',*,*,#1208,.T.);
#1210=DIRECTION('',(0.,0.,-1.));
#1211=VECTOR('',#1210,1.);
#1212=CARTESIAN_POINT('',(19.1389,15.8307359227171,12.7));
#1213=LINE('',#1212,#1211);
#1214=CARTESIAN_POINT('',(19.1389,15.8307359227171,12.7));
#1215=VERTEX_POINT('',#1214);
#1216=EDGE_CURVE('E573',#1215,#1207,#1213,.T.);
#1217=ORIENTED_EDGE('',*,*,#1216,.F.);
#1218=DIRECTION('',(0.,1.,0.));
#1219=VECTOR('',#1218,1.);
#1220=CARTESIAN_POINT('',(19.1389,10.7491294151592,12.7));
#1221=LINE('',#1220,#1219);
#1222=EDGE_CURVE('E772',#1184,#1215,#1221,.T.);
#1223=ORIENTED_EDGE('',*,*,#1222,.F.);
#1224=ORIENTED_EDGE('',*,*,#1185,.T.);
#1225=EDGE_LOOP('',(#1209,#1217,#1223,#1224));
#1226=FACE_BOUND('',#1225,.T.);
#1227=ADVANCED_FACE('F965',(#1226),#1201,.F.);
#1228=CARTESIAN_POINT('',(19.1389,15.8307359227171,12.7));
#1229=DIRECTION('',(-0.793466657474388,0.608613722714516,0.));
#1230=DIRECTION('',(-0.608613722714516,-0.793466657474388,0.));
#1231=AXIS2_PLACEMENT_3D('',#1228,#1229,#1230);
#1232=PLANE('',#1231);
#1233=DIRECTION('',(0.608613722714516,0.793466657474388,0.));
#1234=VECTOR('',#1233,1.);
#1235=CARTESIAN_POINT('',(19.1389,15.8307359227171,-12.7));
#1236=LINE('',#1235,#1234);
#1237=CARTESIAN_POINT('',(21.1624286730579,18.4688666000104,-12.7));
#1238=VERTEX_POINT('',#1237);
#1239=EDGE_CURVE('E494',#1207,#1238,#1236,.T.);
#1240=ORIENTED_EDGE('',*,*,#1239,.T.);
#1241=DIRECTION('',(0.,0.,-1.));
#1242=VECTOR('',#1241,1.);
#1243=CARTESIAN_POINT('',(21.1624286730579,18.4688666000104,12.7));
#1244=LINE('',#1243,#1242);
#1245=CARTESIAN_POINT('',(21.1624286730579,18.4688666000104,12.7));
#1246=VERTEX_POINT('',#1245);
#1247=EDGE_CURVE('E570',#1246,#1238,#1244,.T.);
#1248=ORIENTED_EDGE('',*,*,#1247,.F.);
#1249=DIRECTION('',(0.608613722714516,0.793466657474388,0.));
#1250=VECTOR('',#1249,1.);
#1251=CARTESIAN_POINT('',(19.1389,15.8307359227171,12.7));
#1252=LINE('',#1251,#1250);
#1253=EDGE_CURVE('E774',#1215,#1246,#1252,.T.);
#1254=ORIENTED_EDGE('',*,*,#1253,.F.);
#1255=ORIENTED_EDGE('',*,*,#1216,.T.);
#1256=EDGE_LOOP('',(#1240,#1248,#1254,#1255));
#1257=FACE_BOUND('',#1256,.T.);
#1258=ADVANCED_FACE('F969',(#1257),#1232,.F.);
#1259=CARTESIAN_POINT('',(17.6403,19.1676263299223,12.7));
#1260=DIRECTION('',(0.,0.,-1.));
#1261=DIRECTION('',(-1.,0.,0.));
#1262=AXIS2_PLACEMENT_3D('',#1259,#1260,#1261);
#1263=CYLINDRICAL_SURFACE('',#1262,3.59077367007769);
#1264=CARTESIAN_POINT('',(17.6403,19.1676263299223,-12.7));
#1265=DIRECTION('',(0.,0.,1.));
#1266=DIRECTION('',(-1.,0.,0.));
#1267=AXIS2_PLACEMENT_3D('',#1264,#1265,#1266);
#1268=CIRCLE('',#1267,3.59077367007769);
#1269=CARTESIAN_POINT('',(17.6403,22.7584,-12.7));
#1270=VERTEX_POINT('',#1269);
#1271=EDGE_CURVE('E496',#1238,#1270,#1268,.T.);
#1272=ORIENTED_EDGE('',*,*,#1271,.T.);
#1273=DIRECTION('',(0.,0.,-1.));
#1274=VECTOR('',#1273,1.);
#1275=CARTESIAN_POINT('',(17.6403,22.7584,12.7));
#1276=LINE('',#1275,#1274);
#1277=CARTESIAN_POINT('',(17.6403,22.7584,12.7));
#1278=VERTEX_POINT('',#1277);
#1279=EDGE_CURVE('E567',#1278,#1270,#1276,.T.);
#1280=ORIENTED_EDGE('',*,*,#1279,.F.);
#1281=CARTESIAN_POINT('',(17.6403,19.1676263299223,12.7));
#1282=DIRECTION('',(0.,0.,1.));
#1283=DIRECTION('',(-1.,0.,0.));
#1284=AXIS2_PLACEMENT_3D('',#1281,#1282,#1283);
#1285=CIRCLE('',#1284,3.59077367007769);
#1286=EDGE_CURVE('E776',#1246,#1278,#1285,.T.);
#1287=ORIENTED_EDGE('',*,*,#1286,.F.);
#1288=ORIENTED_EDGE('',*,*,#1247,.T.);
#1289=EDGE_LOOP('',(#1272,#1280,#1287,#1288));
#1290=FACE_BOUND('',#1289,.T.);
#1291=ADVANCED_FACE('F973',(#1290),#1263,.T.);
#1292=CARTESIAN_POINT('',(17.6403,22.7584,12.7));
#1293=DIRECTION('',(0.,-1.,0.));
#1294=DIRECTION('',(1.,0.,0.));
#1295=AXIS2_PLACEMENT_3D('',#1292,#1293,#1294);
#1296=PLANE('',#1295);
#1297=DIRECTION('',(-1.,0.,0.));
#1298=VECTOR('',#1297,1.);
#1299=CARTESIAN_POINT('',(17.6403,22.7584,-12.7));
#1300=LINE('',#1299,#1298);
#1301=CARTESIAN_POINT('',(14.7032736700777,22.7584,-12.7));
#1302=VERTEX_POINT('',#1301);
#1303=EDGE_CURVE('E498',#1270,#1302,#1300,.T.);
#1304=ORIENTED_EDGE('',*,*,#1303,.T.);
#1305=DIRECTION('',(0.,0.,-1.));
#1306=VECTOR('',#1305,1.);
#1307=CARTESIAN_POINT('',(14.7032736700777,22.7584,12.7));
#1308=LINE('',#1307,#1306);
#1309=CARTESIAN_POINT('',(14.7032736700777,22.7584,12.7));
#1310=VERTEX_POINT('',#1309);
#1311=EDGE_CURVE('E564',#1310,#1302,#1308,.T.);
#1312=ORIENTED_EDGE('',*,*,#1311,.F.);
#1313=DIRECTION('',(-1.,0.,0.));
#1314=VECTOR('',#1313,1.);
#1315=CARTESIAN_POINT('',(17.6403,22.7584,12.7));
#1316=LINE('',#1315,#1314);
#1317=EDGE_CURVE('E778',#1278,#1310,#1316,.T.);
#1318=ORIENTED_EDGE('',*,*,#1317,.F.);
#1319=ORIENTED_EDGE('',*,*,#1279,.T.);
#1320=EDGE_LOOP('',(#1304,#1312,#1318,#1319));
#1321=FACE_BOUND('',#1320,.T.);
#1322=ADVANCED_FACE('F977',(#1321),#1296,.F.);
#1323=CARTESIAN_POINT('',(14.7032736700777,19.1676263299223,12.7));
#1324=DIRECTION('',(0.,0.,-1.));
#1325=DIRECTION('',(-1.,0.,0.));
#1326=AXIS2_PLACEMENT_3D('',#1323,#1324,#1325);
#1327=CYLINDRICAL_SURFACE('',#1326,3.5907736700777);
#1328=CARTESIAN_POINT('',(14.7032736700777,19.1676263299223,-12.7));
#1329=DIRECTION('',(0.,0.,1.));
#1330=DIRECTION('',(-1.,0.,0.));
#1331=AXIS2_PLACEMENT_3D('',#1328,#1329,#1330);
#1332=CIRCLE('',#1331,3.5907736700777);
#1333=CARTESIAN_POINT('',(11.1125,19.1676263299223,-12.7));
#1334=VERTEX_POINT('',#1333);
#1335=EDGE_CURVE('E500',#1302,#1334,#1332,.T.);
#1336=ORIENTED_EDGE('',*,*,#1335,.T.);
#1337=DIRECTION('',(0.,0.,-1.));
#1338=VECTOR('',#1337,1.);
#1339=CARTESIAN_POINT('',(11.1125,19.1676263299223,12.7));
#1340=LINE('',#1339,#1338);
#1341=CARTESIAN_POINT('',(11.1125,19.1676263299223,12.7));
#1342=VERTEX_POINT('',#1341);
#1343=EDGE_CURVE('E561',#1342,#1334,#1340,.T.);
#1344=ORIENTED_EDGE('',*,*,#1343,.F.);
#1345=CARTESIAN_POINT('',(14.7032736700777,19.1676263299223,12.7));
#1346=DIRECTION('',(0.,0.,1.));
#1347=DIRECTION('',(-1.,0.,0.));
#1348=AXIS2_PLACEMENT_3D('',#1345,#1346,#1347);
#1349=CIRCLE('',#1348,3.5907736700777);
#1350=EDGE_CURVE('E780',#1310,#1342,#1349,.T.);
#1351=ORIENTED_EDGE('',*,*,#1350,.F.);
#1352=ORIENTED_EDGE('',*,*,#1311,.T.);
#1353=EDGE_LOOP('',(#1336,#1344,#1351,#1352));
#1354=FACE_BOUND('',#1353,.T.);
#1355=ADVANCED_FACE('F981',(#1354),#1327,.T.);
#1356=CARTESIAN_POINT('',(11.1125,19.1676263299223,12.7));
#1357=DIRECTION('',(1.,0.,0.));
#1358=DIRECTION('',(0.,1.,0.));
#1359=AXIS2_PLACEMENT_3D('',#1356,#1357,#1358);
#1360=PLANE('',#1359);
#1361=DIRECTION('',(0.,-1.,0.));
#1362=VECTOR('',#1361,1.);
#1363=CARTESIAN_POINT('',(11.1125,19.1676263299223,-12.7));
#1364=LINE('',#1363,#1362);
#1365=CARTESIAN_POINT('',(11.1125,15.61465,-12.7));
#1366=VERTEX_POINT('',#1365);
#1367=EDGE_CURVE('E502',#1334,#1366,#1364,.T.);
#1368=ORIENTED_EDGE('',*,*,#1367,.T.);
#1369=DIRECTION('',(0.,0.,-1.));
#1370=VECTOR('',#1369,1.);
#1371=CARTESIAN_POINT('',(11.1125,15.61465,12.7));
#1372=LINE('',#1371,#1370);
#1373=CARTESIAN_POINT('',(11.1125,15.61465,12.7));
#1374=VERTEX_POINT('',#1373);
#1375=EDGE_CURVE('E558',#1374,#1366,#1372,.T.);
#1376=ORIENTED_EDGE('',*,*,#1375,.F.);
#1377=DIRECTION('',(0.,-1.,0.));
#1378=VECTOR('',#1377,1.);
#1379=CARTESIAN_POINT('',(11.1125,19.1676263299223,12.7));
#1380=LINE('',#1379,#1378);
#1381=EDGE_CURVE('E782',#1342,#1374,#1380,.T.);
#1382=ORIENTED_EDGE('',*,*,#1381,.F.);
#1383=ORIENTED_EDGE('',*,*,#1343,.T.);
#1384=EDGE_LOOP('',(#1368,#1376,#1382,#1383));
#1385=FACE_BOUND('',#1384,.T.);
#1386=ADVANCED_FACE('F985',(#1385),#1360,.F.);
#1387=CARTESIAN_POINT('',(11.1125,15.61465,12.7));
#1388=DIRECTION('',(0.,1.,0.));
#1389=DIRECTION('',(-1.,0.,0.));
#1390=AXIS2_PLACEMENT_3D('',#1387,#1388,#1389);
#1391=PLANE('',#1390);
#1392=DIRECTION('',(1.,0.,0.));
#1393=VECTOR('',#1392,1.);
#1394=CARTESIAN_POINT('',(11.1125,15.61465,-12.7));
#1395=LINE('',#1394,#1393);
#1396=CARTESIAN_POINT('',(12.6111,15.61465,-12.7));
#1397=VERTEX_POINT('',#1396);
#1398=EDGE_CURVE('E504',#1366,#1397,#1395,.T.);
#1399=ORIENTED_EDGE('',*,*,#1398,.T.);
#1400=DIRECTION('',(0.,0.,-1.));
#1401=VECTOR('',#1400,1.);
#1402=CARTESIAN_POINT('',(12.6111,15.61465,12.7));
#1403=LINE('',#1402,#1401);
#1404=CARTESIAN_POINT('',(12.6111,15.61465,12.7));
#1405=VERTEX_POINT('',#1404);
#1406=EDGE_CURVE('E555',#1405,#1397,#1403,.T.);
#1407=ORIENTED_EDGE('',*,*,#1406,.F.);
#1408=DIRECTION('',(1.,0.,0.));
#1409=VECTOR('',#1408,1.);
#1410=CARTESIAN_POINT('',(11.1125,15.61465,12.7));
#1411=LINE('',#1410,#1409);
#1412=EDGE_CURVE('E784',#1374,#1405,#1411,.T.);
#1413=ORIENTED_EDGE('',*,*,#1412,.F.);
#1414=ORIENTED_EDGE('',*,*,#1375,.T.);
#1415=EDGE_LOOP('',(#1399,#1407,#1413,#1414));
#1416=FACE_BOUND('',#1415,.T.);
#1417=ADVANCED_FACE('F989',(#1416),#1391,.F.);
#1418=CARTESIAN_POINT('',(12.6111,19.1676263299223,12.7));
#1419=DIRECTION('',(-1.,0.,0.));
#1420=DIRECTION('',(0.,-1.,0.));
#1421=AXIS2_PLACEMENT_3D('',#1418,#1419,#1420);
#1422=PLANE('',#1421);
#1423=DIRECTION('',(0.,1.,0.));
#1424=VECTOR('',#1423,1.);
#1425=CARTESIAN_POINT('',(12.6111,19.1676263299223,-12.7));
#1426=LINE('',#1425,#1424);
#1427=CARTESIAN_POINT('',(12.6111,19.1676263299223,-12.7));
#1428=VERTEX_POINT('',#1427);
#1429=EDGE_CURVE('E506',#1397,#1428,#1426,.T.);
#1430=ORIENTED_EDGE('',*,*,#1429,.T.);
#1431=DIRECTION('',(0.,0.,-1.));
#1432=VECTOR('',#1431,1.);
#1433=CARTESIAN_POINT('',(12.6111,19.1676263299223,12.7));
#1434=LINE('',#1433,#1432);
#1435=CARTESIAN_POINT('',(12.6111,19.1676263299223,12.7));
#1436=VERTEX_POINT('',#1435);
#1437=EDGE_CURVE('E552',#1436,#1428,#1434,.T.);
#1438=ORIENTED_EDGE('',*,*,#1437,.F.);
#1439=DIRECTION('',(0.,1.,0.));
#1440=VECTOR('',#1439,1.);
#1441=CARTESIAN_POINT('',(12.6111,19.1676263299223,12.7));
#1442=LINE('',#1441,#1440);
#1443=EDGE_CURVE('E786',#1405,#1436,#1442,.T.);
#1444=ORIENTED_EDGE('',*,*,#1443,.F.);
#1445=ORIENTED_EDGE('',*,*,#1406,.T.);
#1446=EDGE_LOOP('',(#1430,#1438,#1444,#1445));
#1447=FACE_BOUND('',#1446,.T.);
#1448=ADVANCED_FACE('F993',(#1447),#1422,.F.);
#1449=CARTESIAN_POINT('',(14.7032736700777,19.1676263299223,12.7));
#1450=DIRECTION('',(0.,0.,-1.));
#1451=DIRECTION('',(-1.,0.,0.));
#1452=AXIS2_PLACEMENT_3D('',#1449,#1450,#1451);
#1453=CYLINDRICAL_SURFACE('',#1452,2.09217367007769);
#1454=CARTESIAN_POINT('',(14.7032736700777,19.1676263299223,-12.7));
#1455=DIRECTION('',(0.,0.,-1.));
#1456=DIRECTION('',(-1.,0.,0.));
#1457=AXIS2_PLACEMENT_3D('',#1454,#1455,#1456);
#1458=CIRCLE('',#1457,2.09217367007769);
#1459=CARTESIAN_POINT('',(14.7032736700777,21.2598,-12.7));
#1460=VERTEX_POINT('',#1459);
#1461=EDGE_CURVE('E508',#1428,#1460,#1458,.T.);
#1462=ORIENTED_EDGE('',*,*,#1461,.T.);
#1463=DIRECTION('',(0.,0.,-1.));
#1464=VECTOR('',#1463,1.);
#1465=CARTESIAN_POINT('',(14.7032736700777,21.2598,12.7));
#1466=LINE('',#1465,#1464);
#1467=CARTESIAN_POINT('',(14.7032736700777,21.2598,12.7));
#1468=VERTEX_POINT('',#1467);
#1469=EDGE_CURVE('E549',#1468,#1460,#1466,.T.);
#1470=ORIENTED_EDGE('',*,*,#1469,.F.);
#1471=CARTESIAN_POINT('',(14.7032736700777,19.1676263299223,12.7));
#1472=DIRECTION('',(0.,0.,-1.));
#1473=DIRECTION('',(-1.,0.,0.));
#1474=AXIS2_PLACEMENT_3D('',#1471,#1472,#1473);
#1475=CIRCLE('',#1474,2.09217367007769);
#1476=EDGE_CURVE('E788',#1436,#1468,#1475,.T.);
#1477=ORIENTED_EDGE('',*,*,#1476,.F.);
#1478=ORIENTED_EDGE('',*,*,#1437,.T.);
#1479=EDGE_LOOP('',(#1462,#1470,#1477,#1478));
#1480=FACE_BOUND('',#1479,.T.);
#1481=ADVANCED_FACE('F997',(#1480),#1453,.F.);
#1482=CARTESIAN_POINT('',(17.6403,21.2598,12.7));
#1483=DIRECTION('',(0.,1.,0.));
#1484=DIRECTION('',(0.,0.,1.));
#1485=AXIS2_PLACEMENT_3D('',#1482,#1483,#1484);
#1486=PLANE('',#1485);
#1487=DIRECTION('',(1.,0.,0.));
#1488=VECTOR('',#1487,1.);
#1489=CARTESIAN_POINT('',(17.6403,21.2598,-12.7));
#1490=LINE('',#1489,#1488);
#1491=CARTESIAN_POINT('',(17.6403,21.2598,-12.7));
#1492=VERTEX_POINT('',#1491);
#1493=EDGE_CURVE('E510',#1460,#1492,#1490,.T.);
#1494=ORIENTED_EDGE('',*,*,#1493,.T.);
#1495=DIRECTION('',(0.,0.,-1.));
#1496=VECTOR('',#1495,1.);
#1497=CARTESIAN_POINT('',(17.6403,21.2598,12.7));
#1498=LINE('',#1497,#1496);
#1499=CARTESIAN_POINT('',(17.6403,21.2598,12.7));
#1500=VERTEX_POINT('',#1499);
#1501=EDGE_CURVE('E546',#1500,#1492,#1498,.T.);
#1502=ORIENTED_EDGE('',*,*,#1501,.F.);
#1503=DIRECTION('',(1.,0.,0.));
#1504=VECTOR('',#1503,1.);
#1505=CARTESIAN_POINT('',(17.6403,21.2598,12.7));
#1506=LINE('',#1505,#1504);
#1507=EDGE_CURVE('E790',#1468,#1500,#1506,.T.);
#1508=ORIENTED_EDGE('',*,*,#1507,.F.);
#1509=ORIENTED_EDGE('',*,*,#1469,.T.);
#1510=EDGE_LOOP('',(#1494,#1502,#1508,#1509));
#1511=FACE_BOUND('',#1510,.T.);
#1512=ADVANCED_FACE('F1001',(#1511),#1486,.F.);
#1513=CARTESIAN_POINT('',(17.6403,19.1676263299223,12.7));
#1514=DIRECTION('',(0.,0.,-1.));
#1515=DIRECTION('',(-1.,0.,0.));
#1516=AXIS2_PLACEMENT_3D('',#1513,#1514,#1515);
#1517=CYLINDRICAL_SURFACE('',#1516,2.09217367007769);
#1518=CARTESIAN_POINT('',(17.6403,19.1676263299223,-12.7));
#1519=DIRECTION('',(0.,0.,-1.));
#1520=DIRECTION('',(-1.,0.,0.));
#1521=AXIS2_PLACEMENT_3D('',#1518,#1519,#1520);
#1522=CIRCLE('',#1521,2.09217367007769);
#1523=CARTESIAN_POINT('',(19.7298825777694,19.0635335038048,-12.7));
#1524=VERTEX_POINT('',#1523);
#1525=EDGE_CURVE('E512',#1492,#1524,#1522,.T.);
#1526=ORIENTED_EDGE('',*,*,#1525,.T.);
#1527=DIRECTION('',(0.,0.,-1.));
#1528=VECTOR('',#1527,1.);
#1529=CARTESIAN_POINT('',(19.7298825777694,19.0635335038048,12.7));
#1530=LINE('',#1529,#1528);
#1531=CARTESIAN_POINT('',(19.7298825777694,19.0635335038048,12.7));
#1532=VERTEX_POINT('',#1531);
#1533=EDGE_CURVE('E543',#1532,#1524,#1530,.T.);
#1534=ORIENTED_EDGE('',*,*,#1533,.F.);
#1535=CARTESIAN_POINT('',(17.6403,19.1676263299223,12.7));
#1536=DIRECTION('',(0.,0.,-1.));
#1537=DIRECTION('',(-1.,0.,0.));
#1538=AXIS2_PLACEMENT_3D('',#1535,#1536,#1537);
#1539=CIRCLE('',#1538,2.09217367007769);
#1540=EDGE_CURVE('E792',#1500,#1532,#1539,.T.);
#1541=ORIENTED_EDGE('',*,*,#1540,.F.);
#1542=ORIENTED_EDGE('',*,*,#1501,.T.);
#1543=EDGE_LOOP('',(#1526,#1534,#1541,#1542));
#1544=FACE_BOUND('',#1543,.T.);
#1545=ADVANCED_FACE('F1005',(#1544),#1517,.F.);
#1546=CARTESIAN_POINT('',(17.6403,16.3392865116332,12.7));
#1547=DIRECTION('',(0.793466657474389,-0.608613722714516,0.));
#1548=DIRECTION('',(0.608613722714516,0.793466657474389,0.));
#1549=AXIS2_PLACEMENT_3D('',#1546,#1547,#1548);
#1550=PLANE('',#1549);
#1551=DIRECTION('',(-0.608613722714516,-0.793466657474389,0.));
#1552=VECTOR('',#1551,1.);
#1553=CARTESIAN_POINT('',(17.6403,16.3392865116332,-12.7));
#1554=LINE('',#1553,#1552);
#1555=CARTESIAN_POINT('',(17.6403,16.3392865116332,-12.7));
#1556=VERTEX_POINT('',#1555);
#1557=EDGE_CURVE('E514',#1524,#1556,#1554,.T.);
#1558=ORIENTED_EDGE('',*,*,#1557,.T.);
#1559=DIRECTION('',(0.,0.,-1.));
#1560=VECTOR('',#1559,1.);
#1561=CARTESIAN_POINT('',(17.6403,16.3392865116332,12.7));
#1562=LINE('',#1561,#1560);
#1563=CARTESIAN_POINT('',(17.6403,16.3392865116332,12.7));
#1564=VERTEX_POINT('',#1563);
#1565=EDGE_CURVE('E540',#1564,#1556,#1562,.T.);
#1566=ORIENTED_EDGE('',*,*,#1565,.F.);
#1567=DIRECTION('',(-0.608613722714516,-0.793466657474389,0.));
#1568=VECTOR('',#1567,1.);
#1569=CARTESIAN_POINT('',(17.6403,16.3392865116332,12.7));
#1570=LINE('',#1569,#1568);
#1571=EDGE_CURVE('E794',#1532,#1564,#1570,.T.);
#1572=ORIENTED_EDGE('',*,*,#1571,.F.);
#1573=ORIENTED_EDGE('',*,*,#1533,.T.);
#1574=EDGE_LOOP('',(#1558,#1566,#1572,#1573));
#1575=FACE_BOUND('',#1574,.T.);
#1576=ADVANCED_FACE('F1009',(#1575),#1550,.F.);
#1577=CARTESIAN_POINT('',(17.6403,10.178602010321,12.7));
#1578=DIRECTION('',(1.,0.,0.));
#1579=DIRECTION('',(0.,0.,-1.));
#1580=AXIS2_PLACEMENT_3D('',#1577,#1578,#1579);
#1581=PLANE('',#1580);
#1582=DIRECTION('',(0.,-1.,0.));
#1583=VECTOR('',#1582,1.);
#1584=CARTESIAN_POINT('',(17.6403,10.178602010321,-12.7));
#1585=LINE('',#1584,#1583);
#1586=CARTESIAN_POINT('',(17.6403,10.178602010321,-12.7));
#1587=VERTEX_POINT('',#1586);
#1588=EDGE_CURVE('E516',#1556,#1587,#1585,.T.);
#1589=ORIENTED_EDGE('',*,*,#1588,.T.);
#1590=DIRECTION('',(0.,0.,-1.));
#1591=VECTOR('',#1590,1.);
#1592=CARTESIAN_POINT('',(17.6403,10.178602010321,12.7));
#1593=LINE('',#1592,#1591);
#1594=CARTESIAN_POINT('',(17.6403,10.178602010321,12.7));
#1595=VERTEX_POINT('',#1594);
#1596=EDGE_CURVE('E537',#1595,#1587,#1593,.T.);
#1597=ORIENTED_EDGE('',*,*,#1596,.F.);
#1598=DIRECTION('',(0.,-1.,0.));
#1599=VECTOR('',#1598,1.);
#1600=CARTESIAN_POINT('',(17.6403,10.178602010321,12.7));
#1601=LINE('',#1600,#1599);
#1602=EDGE_CURVE('E796',#1564,#1595,#1601,.T.);
#1603=ORIENTED_EDGE('',*,*,#1602,.F.);
#1604=ORIENTED_EDGE('',*,*,#1565,.T.);
#1605=EDGE_LOOP('',(#1589,#1597,#1603,#1604));
#1606=FACE_BOUND('',#1605,.T.);
#1607=ADVANCED_FACE('F1013',(#1606),#1581,.F.);
#1608=CARTESIAN_POINT('',(17.6403,10.178602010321,12.7));
#1609=DIRECTION('',(0.746819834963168,0.665026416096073,0.));
#1610=DIRECTION('',(-0.665026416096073,0.746819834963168,0.));
#1611=AXIS2_PLACEMENT_3D('',#1608,#1609,#1610);
#1612=PLANE('',#1611);
#1613=DIRECTION('',(0.665026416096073,-0.746819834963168,0.));
#1614=VECTOR('',#1613,1.);
#1615=CARTESIAN_POINT('',(17.6403,10.178602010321,-12.7));
#1616=LINE('',#1615,#1614);
#1617=CARTESIAN_POINT('',(19.1389,8.49568509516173,-12.7));
#1618=VERTEX_POINT('',#1617);
#1619=EDGE_CURVE('E518',#1587,#1618,#1616,.T.);
#1620=ORIENTED_EDGE('',*,*,#1619,.T.);
#1621=DIRECTION('',(0.,0.,-1.));
#1622=VECTOR('',#1621,1.);
#1623=CARTESIAN_POINT('',(19.1389,8.49568509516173,12.7));
#1624=LINE('',#1623,#1622);
#1625=CARTESIAN_POINT('',(19.1389,8.49568509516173,12.7));
#1626=VERTEX_POINT('',#1625);
#1627=EDGE_CURVE('E534',#1626,#1618,#1624,.T.);
#1628=ORIENTED_EDGE('',*,*,#1627,.F.);
#1629=DIRECTION('',(0.665026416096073,-0.746819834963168,0.));
#1630=VECTOR('',#1629,1.);
#1631=CARTESIAN_POINT('',(17.6403,10.178602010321,12.7));
#1632=LINE('',#1631,#1630);
#1633=EDGE_CURVE('E798',#1595,#1626,#1632,.T.);
#1634=ORIENTED_EDGE('',*,*,#1633,.F.);
#1635=ORIENTED_EDGE('',*,*,#1596,.T.);
#1636=EDGE_LOOP('',(#1620,#1628,#1634,#1635));
#1637=FACE_BOUND('',#1636,.T.);
#1638=ADVANCED_FACE('F1017',(#1637),#1612,.F.);
#1639=CARTESIAN_POINT('',(19.1389,-4.25388509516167,12.7));
#1640=DIRECTION('',(1.,0.,0.));
#1641=DIRECTION('',(0.,1.,0.));
#1642=AXIS2_PLACEMENT_3D('',#1639,#1640,#1641);
#1643=PLANE('',#1642);
#1644=DIRECTION('',(0.,-1.,0.));
#1645=VECTOR('',#1644,1.);
#1646=CARTESIAN_POINT('',(19.1389,-4.25388509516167,-12.7));
#1647=LINE('',#1646,#1645);
#1648=CARTESIAN_POINT('',(19.1389,-4.25388509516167,-12.7));
#1649=VERTEX_POINT('',#1648);
#1650=EDGE_CURVE('E520',#1618,#1649,#1647,.T.);
#1651=ORIENTED_EDGE('',*,*,#1650,.T.);
#1652=DIRECTION('',(0.,0.,-1.));
#1653=VECTOR('',#1652,1.);
#1654=CARTESIAN_POINT('',(19.1389,-4.25388509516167,12.7));
#1655=LINE('',#1654,#1653);
#1656=CARTESIAN_POINT('',(19.1389,-4.25388509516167,12.7));
#1657=VERTEX_POINT('',#1656);
#1658=EDGE_CURVE('E531',#1657,#1649,#1655,.T.);
#1659=ORIENTED_EDGE('',*,*,#1658,.F.);
#1660=DIRECTION('',(0.,-1.,0.));
#1661=VECTOR('',#1660,1.);
#1662=CARTESIAN_POINT('',(19.1389,-4.25388509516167,12.7));
#1663=LINE('',#1662,#1661);
#1664=EDGE_CURVE('E800',#1626,#1657,#1663,.T.);
#1665=ORIENTED_EDGE('',*,*,#1664,.F.);
#1666=ORIENTED_EDGE('',*,*,#1627,.T.);
#1667=EDGE_LOOP('',(#1651,#1659,#1665,#1666));
#1668=FACE_BOUND('',#1667,.T.);
#1669=ADVANCED_FACE('F806',(#1668),#1643,.F.);
#1670=CARTESIAN_POINT('',(17.6403,-5.93680201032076,12.7));
#1671=DIRECTION('',(0.746819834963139,-0.665026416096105,0.));
#1672=DIRECTION('',(0.665026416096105,0.746819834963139,0.));
#1673=AXIS2_PLACEMENT_3D('',#1670,#1671,#1672);
#1674=PLANE('',#1673);
#1675=DIRECTION('',(-0.665026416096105,-0.746819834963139,0.));
#1676=VECTOR('',#1675,1.);
#1677=CARTESIAN_POINT('',(17.6403,-5.93680201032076,-12.7));
#1678=LINE('',#1677,#1676);
#1679=CARTESIAN_POINT('',(17.6403,-5.93680201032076,-12.7));
#1680=VERTEX_POINT('',#1679);
#1681=EDGE_CURVE('E522',#1649,#1680,#1678,.T.);
#1682=ORIENTED_EDGE('',*,*,#1681,.T.);
#1683=DIRECTION('',(0.,0.,-1.));
#1684=VECTOR('',#1683,1.);
#1685=CARTESIAN_POINT('',(17.6403,-5.93680201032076,12.7));
#1686=LINE('',#1685,#1684);
#1687=CARTESIAN_POINT('',(17.6403,-5.93680201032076,12.7));
#1688=VERTEX_POINT('',#1687);
#1689=EDGE_CURVE('E408',#1688,#1680,#1686,.T.);
#1690=ORIENTED_EDGE('',*,*,#1689,.F.);
#1691=DIRECTION('',(-0.665026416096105,-0.746819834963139,0.));
#1692=VECTOR('',#1691,1.);
#1693=CARTESIAN_POINT('',(17.6403,-5.93680201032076,12.7));
#1694=LINE('',#1693,#1692);
#1695=EDGE_CURVE('E399',#1657,#1688,#1694,.T.);
#1696=ORIENTED_EDGE('',*,*,#1695,.F.);
#1697=ORIENTED_EDGE('',*,*,#1658,.T.);
#1698=EDGE_LOOP('',(#1682,#1690,#1696,#1697));
#1699=FACE_BOUND('',#1698,.T.);
#1700=ADVANCED_FACE('F810',(#1699),#1674,.F.);
#1701=CARTESIAN_POINT('',(17.6403,-13.979525,12.7));
#1702=DIRECTION('',(1.,0.,0.));
#1703=DIRECTION('',(0.,1.,0.));
#1704=AXIS2_PLACEMENT_3D('',#1701,#1702,#1703);
#1705=PLANE('',#1704);
#1706=DIRECTION('',(0.,-1.,0.));
#1707=VECTOR('',#1706,1.);
#1708=CARTESIAN_POINT('',(17.6403,-13.979525,-12.7));
#1709=LINE('',#1708,#1707);
#1710=CARTESIAN_POINT('',(17.6403,-13.979525,-12.7));
#1711=VERTEX_POINT('',#1710);
#1712=EDGE_CURVE('E407',#1680,#1711,#1709,.T.);
#1713=ORIENTED_EDGE('',*,*,#1712,.T.);
#1714=DIRECTION('',(0.,0.,-1.));
#1715=VECTOR('',#1714,1.);
#1716=CARTESIAN_POINT('',(17.6403,-13.979525,12.7));
#1717=LINE('',#1716,#1715);
#1718=CARTESIAN_POINT('',(17.6403,-13.979525,12.7));
#1719=VERTEX_POINT('',#1718);
#1720=EDGE_CURVE('E404',#1719,#1711,#1717,.T.);
#1721=ORIENTED_EDGE('',*,*,#1720,.F.);
#1722=DIRECTION('',(0.,-1.,0.));
#1723=VECTOR('',#1722,1.);
#1724=CARTESIAN_POINT('',(17.6403,-13.979525,12.7));
#1725=LINE('',#1724,#1723);
#1726=EDGE_CURVE('E393',#1688,#1719,#1725,.T.);
#1727=ORIENTED_EDGE('',*,*,#1726,.F.);
#1728=ORIENTED_EDGE('',*,*,#1689,.T.);
#1729=EDGE_LOOP('',(#1713,#1721,#1727,#1728));
#1730=FACE_BOUND('',#1729,.T.);
#1731=ADVANCED_FACE('F405',(#1730),#1705,.F.);
#1732=CARTESIAN_POINT('',(17.6403,-13.979525,12.7));
#1733=DIRECTION('',(0.707106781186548,0.707106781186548,0.));
#1734=DIRECTION('',(-0.707106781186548,0.707106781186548,0.));
#1735=AXIS2_PLACEMENT_3D('',#1732,#1733,#1734);
#1736=PLANE('',#1735);
#1737=DIRECTION('',(0.707106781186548,-0.707106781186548,0.));
#1738=VECTOR('',#1737,1.);
#1739=CARTESIAN_POINT('',(17.6403,-13.979525,-12.7));
#1740=LINE('',#1739,#1738);
#1741=CARTESIAN_POINT('',(19.1389,-15.478125,-12.7));
#1742=VERTEX_POINT('',#1741);
#1743=EDGE_CURVE('E222',#1711,#1742,#1740,.T.);
#1744=ORIENTED_EDGE('',*,*,#1743,.T.);
#1745=DIRECTION('',(0.,0.,-1.));
#1746=VECTOR('',#1745,1.);
#1747=CARTESIAN_POINT('',(19.1389,-15.478125,12.7));
#1748=LINE('',#1747,#1746);
#1749=CARTESIAN_POINT('',(19.1389,-15.478125,12.7));
#1750=VERTEX_POINT('',#1749);
#1751=EDGE_CURVE('E409',#1750,#1742,#1748,.T.);
#1752=ORIENTED_EDGE('',*,*,#1751,.F.);
#1753=DIRECTION('',(0.707106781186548,-0.707106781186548,0.));
#1754=VECTOR('',#1753,1.);
#1755=CARTESIAN_POINT('',(17.6403,-13.979525,12.7));
#1756=LINE('',#1755,#1754);
#1757=EDGE_CURVE('E397',#1719,#1750,#1756,.T.);
#1758=ORIENTED_EDGE('',*,*,#1757,.F.);
#1759=ORIENTED_EDGE('',*,*,#1720,.T.);
#1760=EDGE_LOOP('',(#1744,#1752,#1758,#1759));
#1761=FACE_BOUND('',#1760,.T.);
#1762=ADVANCED_FACE('F411',(#1761),#1736,.F.);
#1763=CARTESIAN_POINT('',(17.6403,-15.478125,12.7));
#1764=DIRECTION('',(0.,0.,-1.));
#1765=DIRECTION('',(-1.,0.,0.));
#1766=AXIS2_PLACEMENT_3D('',#1763,#1764,#1765);
#1767=CYLINDRICAL_SURFACE('',#1766,1.4986);
#1768=CARTESIAN_POINT('',(17.6403,-15.478125,-12.7));
#1769=DIRECTION('',(0.,0.,-1.));
#1770=DIRECTION('',(-1.,0.,0.));
#1771=AXIS2_PLACEMENT_3D('',#1768,#1769,#1770);
#1772=CIRCLE('',#1771,1.4986);
#1773=EDGE_CURVE('E228',#1742,#30,#1772,.T.);
#1774=ORIENTED_EDGE('',*,*,#1773,.T.);
#1775=ORIENTED_EDGE('',*,*,#56,.F.);
#1776=CARTESIAN_POINT('',(17.6403,-15.478125,12.7));
#1777=DIRECTION('',(0.,0.,-1.));
#1778=DIRECTION('',(-1.,0.,0.));
#1779=AXIS2_PLACEMENT_3D('',#1776,#1777,#1778);
#1780=CIRCLE('',#1779,1.4986);
#1781=EDGE_CURVE('E49',#1750,#49,#1780,.T.);
#1782=ORIENTED_EDGE('',*,*,#1781,.F.);
#1783=ORIENTED_EDGE('',*,*,#1751,.T.);
#1784=EDGE_LOOP('',(#1774,#1775,#1782,#1783));
#1785=FACE_BOUND('',#1784,.T.);
#1786=ADVANCED_FACE('F814',(#1785),#1767,.F.);
#1787=CARTESIAN_POINT('',(13.7938113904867,-17.794678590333,12.7));
#1788=DIRECTION('',(0.,0.,1.));
#1789=DIRECTION('',(1.,0.,0.));
#1790=AXIS2_PLACEMENT_3D('',#1787,#1788,#1789);
#1791=PLANE('',#1790);
#1792=ORIENTED_EDGE('',*,*,#50,.T.);
#1793=ORIENTED_EDGE('',*,*,#86,.T.);
#1794=ORIENTED_EDGE('',*,*,#119,.T.);
#1795=ORIENTED_EDGE('',*,*,#152,.T.);
#1796=ORIENTED_EDGE('',*,*,#183,.T.);
#1797=ORIENTED_EDGE('',*,*,#214,.T.);
#1798=ORIENTED_EDGE('',*,*,#245,.T.);
#1799=ORIENTED_EDGE('',*,*,#276,.T.);
#1800=ORIENTED_EDGE('',*,*,#307,.T.);
#1801=ORIENTED_EDGE('',*,*,#338,.T.);
#1802=ORIENTED_EDGE('',*,*,#369,.T.);
#1803=ORIENTED_EDGE('',*,*,#402,.T.);
#1804=ORIENTED_EDGE('',*,*,#433,.T.);
#1805=ORIENTED_EDGE('',*,*,#466,.T.);
#1806=ORIENTED_EDGE('',*,*,#497,.T.);
#1807=ORIENTED_EDGE('',*,*,#528,.T.);
#1808=ORIENTED_EDGE('',*,*,#559,.T.);
#1809=ORIENTED_EDGE('',*,*,#592,.T.);
#1810=ORIENTED_EDGE('',*,*,#623,.T.);
#1811=ORIENTED_EDGE('',*,*,#656,.T.);
#1812=ORIENTED_EDGE('',*,*,#687,.T.);
#1813=ORIENTED_EDGE('',*,*,#718,.T.);
#1814=ORIENTED_EDGE('',*,*,#749,.T.);
#1815=ORIENTED_EDGE('',*,*,#780,.T.);
#1816=ORIENTED_EDGE('',*,*,#811,.T.);
#1817=ORIENTED_EDGE('',*,*,#842,.T.);
#1818=ORIENTED_EDGE('',*,*,#873,.T.);
#1819=ORIENTED_EDGE('',*,*,#906,.T.);
#1820=ORIENTED_EDGE('',*,*,#939,.T.);
#1821=ORIENTED_EDGE('',*,*,#970,.T.);
#1822=ORIENTED_EDGE('',*,*,#1003,.T.);
#1823=ORIENTED_EDGE('',*,*,#1036,.T.);
#1824=ORIENTED_EDGE('',*,*,#1067,.T.);
#1825=ORIENTED_EDGE('',*,*,#1098,.T.);
#1826=ORIENTED_EDGE('',*,*,#1129,.T.);
#1827=ORIENTED_EDGE('',*,*,#1160,.T.);
#1828=ORIENTED_EDGE('',*,*,#1191,.T.);
#1829=ORIENTED_EDGE('',*,*,#1222,.T.);
#1830=ORIENTED_EDGE('',*,*,#1253,.T.);
#1831=ORIENTED_EDGE('',*,*,#1286,.T.);
#1832=ORIENTED_EDGE('',*,*,#1317,.T.);
#1833=ORIENTED_EDGE('',*,*,#1350,.T.);
#1834=ORIENTED_EDGE('',*,*,#1381,.T.);
#1835=ORIENTED_EDGE('',*,*,#1412,.T.);
#1836=ORIENTED_EDGE('',*,*,#1443,.T.);
#1837=ORIENTED_EDGE('',*,*,#1476,.T.);
#1838=ORIENTED_EDGE('',*,*,#1507,.T.);
#1839=ORIENTED_EDGE('',*,*,#1540,.T.);
#1840=ORIENTED_EDGE('',*,*,#1571,.T.);
#1841=ORIENTED_EDGE('',*,*,#1602,.T.);
#1842=ORIENTED_EDGE('',*,*,#1633,.T.);
#1843=ORIENTED_EDGE('',*,*,#1664,.T.);
#1844=ORIENTED_EDGE('',*,*,#1695,.T.);
#1845=ORIENTED_EDGE('',*,*,#1726,.T.);
#1846=ORIENTED_EDGE('',*,*,#1757,.T.);
#1847=ORIENTED_EDGE('',*,*,#1781,.T.);
#1848=EDGE_LOOP('',(#1792,#1793,#1794,#1795,#1796,#1797,#1798,#1799,#1800,#1801,#1802,#1803,
#1804,#1805,#1806,#1807,#1808,#1809,#1810,#1811,#1812,#1813,#1814,#1815,#1816,#1817,#1818,#1819,
#1820,#1821,#1822,#1823,#1824,#1825,#1826,#1827,#1828,#1829,#1830,#1831,#1832,#1833,#1834,#1835,
#1836,#1837,#1838,#1839,#1840,#1841,#1842,#1843,#1844,#1845,#1846,#1847));
#1849=FACE_BOUND('',#1848,.T.);
#1850=ADVANCED_FACE('F395',(#1849),#1791,.T.);
#1851=CARTESIAN_POINT('',(13.7938113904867,-17.794678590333,-12.7));
#1852=DIRECTION('',(0.,0.,1.));
#1853=DIRECTION('',(1.,0.,0.));
#1854=AXIS2_PLACEMENT_3D('',#1851,#1852,#1853);
#1855=PLANE('',#1854);
#1856=ORIENTED_EDGE('',*,*,#33,.F.);
#1857=ORIENTED_EDGE('',*,*,#1773,.F.);
#1858=ORIENTED_EDGE('',*,*,#1743,.F.);
#1859=ORIENTED_EDGE('',*,*,#1712,.F.);
#1860=ORIENTED_EDGE('',*,*,#1681,.F.);
#1861=ORIENTED_EDGE('',*,*,#1650,.F.);
#1862=ORIENTED_EDGE('',*,*,#1619,.F.);
#1863=ORIENTED_EDGE('',*,*,#1588,.F.);
#1864=ORIENTED_EDGE('',*,*,#1557,.F.);
#1865=ORIENTED_EDGE('',*,*,#1525,.F.);
#1866=ORIENTED_EDGE('',*,*,#1493,.F.);
#1867=ORIENTED_EDGE('',*,*,#1461,.F.);
#1868=ORIENTED_EDGE('',*,*,#1429,.F.);
#1869=ORIENTED_EDGE('',*,*,#1398,.F.);
#1870=ORIENTED_EDGE('',*,*,#1367,.F.);
#1871=ORIENTED_EDGE('',*,*,#1335,.F.);
#1872=ORIENTED_EDGE('',*,*,#1303,.F.);
#1873=ORIENTED_EDGE('',*,*,#1271,.F.);
#1874=ORIENTED_EDGE('',*,*,#1239,.F.);
#1875=ORIENTED_EDGE('',*,*,#1208,.F.);
#1876=ORIENTED_EDGE('',*,*,#1177,.F.);
#1877=ORIENTED_EDGE('',*,*,#1146,.F.);
#1878=ORIENTED_EDGE('',*,*,#1115,.F.);
#1879=ORIENTED_EDGE('',*,*,#1084,.F.);
#1880=ORIENTED_EDGE('',*,*,#1053,.F.);
#1881=ORIENTED_EDGE('',*,*,#1021,.F.);
#1882=ORIENTED_EDGE('',*,*,#988,.F.);
#1883=ORIENTED_EDGE('',*,*,#956,.F.);
#1884=ORIENTED_EDGE('',*,*,#924,.F.);
#1885=ORIENTED_EDGE('',*,*,#891,.F.);
#1886=ORIENTED_EDGE('',*,*,#859,.F.);
#1887=ORIENTED_EDGE('',*,*,#828,.F.);
#1888=ORIENTED_EDGE('',*,*,#797,.F.);
#1889=ORIENTED_EDGE('',*,*,#766,.F.);
#1890=ORIENTED_EDGE('',*,*,#735,.F.);
#1891=ORIENTED_EDGE('',*,*,#704,.F.);
#1892=ORIENTED_EDGE('',*,*,#673,.F.);
#1893=ORIENTED_EDGE('',*,*,#641,.F.);
#1894=ORIENTED_EDGE('',*,*,#609,.F.);
#1895=ORIENTED_EDGE('',*,*,#577,.F.);
#1896=ORIENTED_EDGE('',*,*,#545,.F.);
#1897=ORIENTED_EDGE('',*,*,#514,.F.);
#1898=ORIENTED_EDGE('',*,*,#483,.F.);
#1899=ORIENTED_EDGE('',*,*,#451,.F.);
#1900=ORIENTED_EDGE('',*,*,#419,.F.);
#1901=ORIENTED_EDGE('',*,*,#387,.F.);
#1902=ORIENTED_EDGE('',*,*,#355,.F.);
#1903=ORIENTED_EDGE('',*,*,#324,.F.);
#1904=ORIENTED_EDGE('',*,*,#293,.F.);
#1905=ORIENTED_EDGE('',*,*,#262,.F.);
#1906=ORIENTED_EDGE('',*,*,#231,.F.);
#1907=ORIENTED_EDGE('',*,*,#200,.F.);
#1908=ORIENTED_EDGE('',*,*,#169,.F.);
#1909=ORIENTED_EDGE('',*,*,#137,.F.);
#1910=ORIENTED_EDGE('',*,*,#104,.F.);
#1911=ORIENTED_EDGE('',*,*,#72,.F.);
#1912=EDGE_LOOP('',(#1856,#1857,#1858,#1859,#1860,#1861,#1862,#1863,#1864,#1865,#1866,#1867,
#1868,#1869,#1870,#1871,#1872,#1873,#1874,#1875,#1876,#1877,#1878,#1879,#1880,#1881,#1882,#1883,
#1884,#1885,#1886,#1887,#1888,#1889,#1890,#1891,#1892,#1893,#1894,#1895,#1896,#1897,#1898,#1899,
#1900,#1901,#1902,#1903,#1904,#1905,#1906,#1907,#1908,#1909,#1910,#1911));
#1913=FACE_BOUND('',#1912,.T.);
#1914=ADVANCED_FACE('F690',(#1913),#1855,.F.);
#1915=CLOSED_SHELL('',(#60,#91,#124,#157,#188,#219,#250,#281,#312,#343,#374,#407,#438,#471,#502,
#533,#564,#597,#628,#661,#692,#723,#754,#785,#816,#847,#878,#911,#944,#975,#1008,#1041,#1072,
#1103,#1134,#1165,#1196,#1227,#1258,#1291,#1322,#1355,#1386,#1417,#1448,#1481,#1512,#1545,#1576,
#1607,#1638,#1669,#1700,#1731,#1762,#1786,#1850,#1914));
#1916=MANIFOLD_SOLID_BREP('B2',#1915);
#1917=ADVANCED_BREP_SHAPE_REPRESENTATION('',(#18,#1916),#14);
#1918=SHAPE_DEFINITION_REPRESENTATION(#9,#1917);
ENDSEC;
END-ISO-10303-21;
